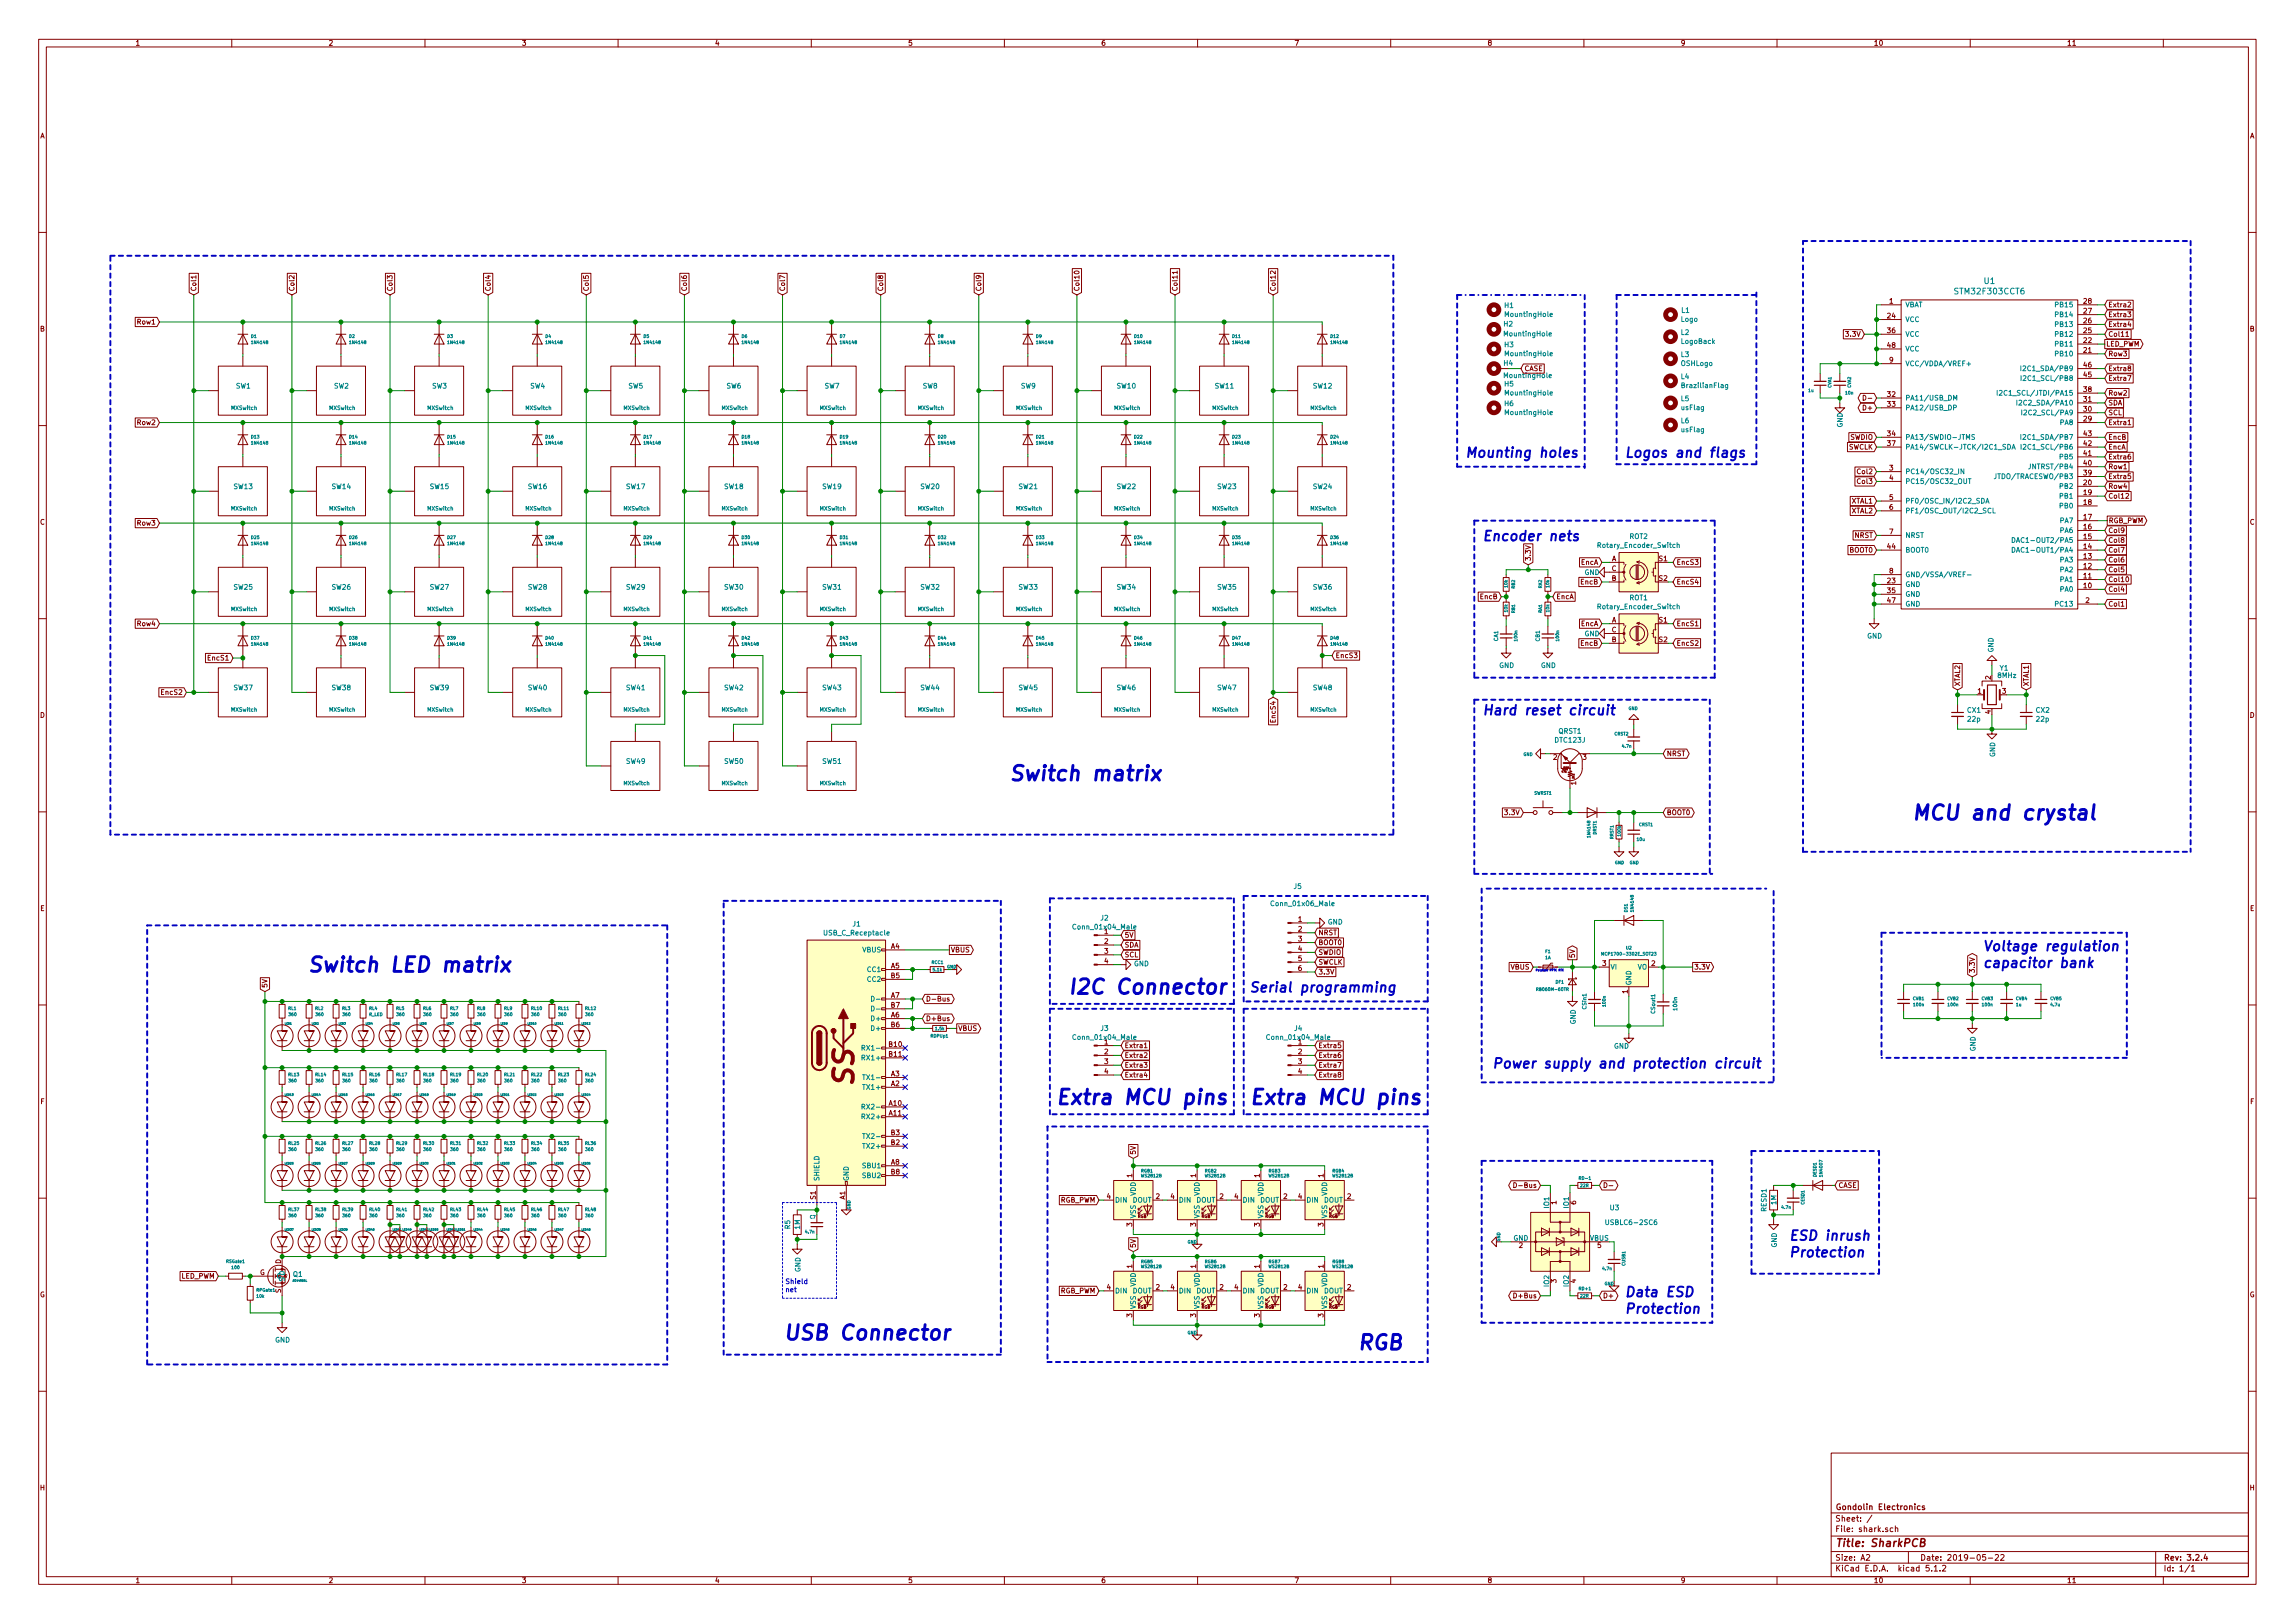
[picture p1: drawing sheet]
<svg xmlns="http://www.w3.org/2000/svg" width="594mm" height="420mm" viewBox="0 0 594 420" stroke-linecap="round" stroke-linejoin="round" font-family="sans-serif">
<defs><g id="words">
<text font-size="7.1" fill="#840000" x="221" y="280.5" transform="rotate(-90 221 280.5)">SS</text>
<g font-size="5.3" fill="#0000c2">
<text x="261" y="202.2">Switch matrix</text>
<text x="494.7" y="212.3">MCU and crystal</text>
<text x="79.4" y="251.7">Switch LED matrix</text>
<text x="276.2" y="257.4">I2C Connector</text>
<text x="273" y="286">Extra MCU pins</text>
<text x="323.2" y="286">Extra MCU pins</text>
<text x="202.6" y="346.9">USB Connector</text>
<text x="351.2" y="349.5">RGB</text>
</g>
<g font-size="3.5" fill="#0000c2">
<text x="379.1" y="118.5">Mounting holes</text>
<text x="420.4" y="118.5">Logos and flags</text>
<text x="383.5" y="140">Encoder nets</text>
<text x="383.5" y="185.1">Hard reset circuit</text>
<text x="513.1" y="246.2">Voltage regulation</text>
<text x="513.1" y="250.5">capacitor bank</text>
<text x="323.2" y="256.9">Serial programming</text>
<text x="386.1" y="276.6">Power supply and protection circuit</text>
<text x="462.9" y="321.1">ESD inrush</text>
<text x="462.9" y="325.5">Protection</text>
<text x="420.4" y="335.8">Data ESD</text>
<text x="420.4" y="340.1">Protection</text>
</g>
<text font-size="2.8" fill="#840000" x="475" y="400.4">Title: SharkPCB</text>
<g font-size="2.1" fill="#008484">
<text x="506.4" y="76.2">STM32F303CCT6</text>
<text x="513.6" y="73.5">U1</text>
</g>
<g font-size="2.1" fill="#840000">
<text x="475" y="393.9">Sheet: /</text>
<text x="475" y="390.9">Gondolin Electronics</text>
<text x="475" y="396.6">File: shark.sch</text>
<text x="475" y="406.8">KiCad E.D.A. kicad 5.1.2</text>
<text x="475" y="404">Size: A2</text>
<text x="497" y="404">Date: 2019-05-22</text>
<text x="560" y="404">Rev: 3.2.4</text>
<text x="560" y="406.8">Id: 1/1</text>
</g>
<g font-size="1.8" fill="#840000">
<text x="35" y="11.8">1</text>
<text x="85" y="11.8">2</text>
<text x="135" y="11.8">3</text>
<text x="185" y="11.8">4</text>
<text x="235" y="11.8">5</text>
<text x="285" y="11.8">6</text>
<text x="335" y="11.8">7</text>
<text x="385" y="11.8">8</text>
<text x="435" y="11.8">9</text>
<text x="485" y="11.8">10</text>
<text x="535" y="11.8">11</text>
<text x="10.4" y="35.8">A</text>
<text x="582.4" y="35.8">A</text>
<text x="50.8" y="75.5" transform="rotate(-90 50.8 75.5)">Col1</text>
<text x="76.2" y="75.5" transform="rotate(-90 76.2 75.5)">Col2</text>
<text x="101.6" y="75.5" transform="rotate(-90 101.6 75.5)">Col3</text>
<text x="127" y="75.5" transform="rotate(-90 127 75.5)">Col4</text>
<text x="152.4" y="75.5" transform="rotate(-90 152.4 75.5)">Col5</text>
<text x="177.8" y="75.5" transform="rotate(-90 177.8 75.5)">Col6</text>
<text x="203.2" y="75.5" transform="rotate(-90 203.2 75.5)">Col7</text>
<text x="228.6" y="75.5" transform="rotate(-90 228.6 75.5)">Col8</text>
<text x="254" y="75.5" transform="rotate(-90 254 75.5)">Col9</text>
<text x="279.4" y="75.5" transform="rotate(-90 279.4 75.5)">Col10</text>
<text x="304.8" y="75.5" transform="rotate(-90 304.8 75.5)">Col11</text>
<text x="330.2" y="75.5" transform="rotate(-90 330.2 75.5)">Col12</text>
<text x="35.7" y="84">Row1</text>
<text x="488.6" y="82.4">24</text>
<text x="489.1" y="78.6">1</text>
<text x="539.4" y="83.7">26</text>
<text x="539.4" y="81.1">27</text>
<text x="539.4" y="78.6">28</text>
<text x="545.7" y="79.5">Extra2</text>
<text x="545.7" y="82.1">Extra3</text>
<text x="10.4" y="85.8">B</text>
<text x="478.1" y="87.2">3.3V</text>
<text x="488.6" y="86.2">36</text>
<text x="539.4" y="88.8">22</text>
<text x="539.4" y="86.2">25</text>
<text x="545.1" y="89.7">LED_PWM</text>
<text x="545.7" y="87.2">Col11</text>
<text x="545.7" y="84.6">Extra4</text>
<text x="582.4" y="85.8">B</text>
<text x="488.6" y="90">48</text>
<text x="489.1" y="93.8">9</text>
<text x="539.4" y="91.3">21</text>
<text x="539.4" y="95.1">46</text>
<text x="545.7" y="92.2">Row3</text>
<text x="394.5" y="96.1">CASE</text>
<text x="539.4" y="101.5">38</text>
<text x="539.4" y="97.7">45</text>
<text x="545.7" y="96.1">Extra8</text>
<text x="545.7" y="98.6">Extra7</text>
<text x="482.6" y="106.2">D+</text>
<text x="488.6" y="102.7">32</text>
<text x="488.6" y="105.3">33</text>
<text x="539.4" y="106.5">30</text>
<text x="539.4" y="104">31</text>
<text x="545.7" y="102.4">Row2</text>
<text x="545.7" y="107.5">SCL</text>
<text x="545.7" y="104.9">SDA</text>
<text x="35.7" y="110">Row2</text>
<text x="478.9" y="113.8">SWDIO</text>
<text x="488.6" y="112.9">34</text>
<text x="539.4" y="109.1">29</text>
<text x="539.4" y="112.9">43</text>
<text x="545.7" y="113.8">EncB</text>
<text x="545.7" y="110">Extra1</text>
<text x="478.5" y="116.4">SWCLK</text>
<text x="488.6" y="115.4">37</text>
<text x="539.4" y="118">41</text>
<text x="539.4" y="115.4">42</text>
<text x="545.7" y="116.4">EncA</text>
<text x="545.7" y="118.9">Extra6</text>
<text x="481.1" y="122.7">Col2</text>
<text x="481.1" y="125.3">Col3</text>
<text x="489.1" y="121.8">3</text>
<text x="489.1" y="124.3">4</text>
<text x="539.4" y="125.6">20</text>
<text x="539.4" y="123.1">39</text>
<text x="539.4" y="120.5">40</text>
<text x="545.7" y="121.5">Row1</text>
<text x="545.7" y="124">Extra5</text>
<text x="479.3" y="130.3">XTAL1</text>
<text x="489.1" y="129.4">5</text>
<text x="489.1" y="131.9">6</text>
<text x="539.4" y="130.7">18</text>
<text x="539.4" y="128.1">19</text>
<text x="545.7" y="126.5">Row4</text>
<text x="545.7" y="129.1">Col12</text>
<text x="10.4" y="135.8">C</text>
<text x="35.7" y="136.1">Row3</text>
<text x="479.3" y="132.9">XTAL2</text>
<text x="539.4" y="137">16</text>
<text x="539.4" y="134.5">17</text>
<text x="545.7" y="138">Col9</text>
<text x="545.8" y="135.4">RGB_PWM</text>
<text x="582.4" y="135.8">C</text>
<text x="478.8" y="143">BOOT0</text>
<text x="480.1" y="139.2">NRST</text>
<text x="488.6" y="142.1">44</text>
<text x="489.1" y="138.3">7</text>
<text x="539.4" y="142.1">14</text>
<text x="539.4" y="139.6">15</text>
<text x="545.7" y="143">Col7</text>
<text x="545.7" y="140.5">Col8</text>
<text x="396.2" y="145.4" transform="rotate(-90 396.2 145.4)">3.3V</text>
<text x="409.3" y="146.2">EncA</text>
<text x="417.2" y="145.3">A</text>
<text x="417.2" y="147.8">C</text>
<text x="429.5" y="145.3">S1</text>
<text x="433.9" y="146.2">EncS3</text>
<text x="489.1" y="148.5">8</text>
<text x="539.4" y="149.7">11</text>
<text x="539.4" y="147.2">12</text>
<text x="539.4" y="144.6">13</text>
<text x="545.7" y="148.1">Col5</text>
<text x="545.7" y="145.6">Col6</text>
<text x="383.3" y="155.1">EncB</text>
<text x="402.8" y="155.1">EncA</text>
<text x="409.3" y="151.3">EncB</text>
<text x="417.2" y="150.4">B</text>
<text x="429.5" y="150.4">S2</text>
<text x="433.9" y="151.3">EncS4</text>
<text x="488.6" y="151">23</text>
<text x="488.6" y="153.5">35</text>
<text x="539.4" y="152.3">10</text>
<text x="545.7" y="150.7">Col10</text>
<text x="545.7" y="153.2">Col4</text>
<text x="417.2" y="161.2">A</text>
<text x="429.5" y="161.2">S1</text>
<text x="488.6" y="156.1">47</text>
<text x="539.9" y="156.1">2</text>
<text x="545.7" y="157">Col1</text>
<text x="35.7" y="162.1">Row4</text>
<text x="409.3" y="162.1">EncA</text>
<text x="409.3" y="167.2">EncB</text>
<text x="417.2" y="166.2">B</text>
<text x="417.2" y="163.7">C</text>
<text x="429.5" y="166.2">S2</text>
<text x="433.9" y="167.2">EncS2</text>
<text x="433.9" y="162.1">EncS1</text>
<text x="54.1" y="171">EncS1</text>
<text x="345.6" y="170.3">EncS3</text>
<text x="42" y="179.9">EncS2</text>
<text x="507.4" y="177.8" transform="rotate(-90 507.4 177.8)">XTAL2</text>
<text x="512" y="179.6">1</text>
<text x="515.3" y="175.9" transform="rotate(-90 515.3 175.9)">2</text>
<text x="518.3" y="179.6">3</text>
<text x="525.1" y="177.8" transform="rotate(-90 525.1 177.8)">XTAL1</text>
<text x="10.4" y="185.8">D</text>
<text x="515.3" y="184.8" transform="rotate(-90 515.3 184.8)">4</text>
<text x="582.4" y="185.8">D</text>
<text x="330.2" y="186.8" transform="rotate(-90 330.2 186.8)">EncS4</text>
<text x="402.1" y="196.7">2</text>
<text x="409.7" y="196.7">3</text>
<text x="431.4" y="195.7">NRST</text>
<text x="408" y="203.2" transform="rotate(-90 408 203.2)">1</text>
<text x="389.9" y="211">3.3V</text>
<text x="431.4" y="211">BOOT0</text>
<text x="10.4" y="235.8">E</text>
<text x="336.1" y="238.6">1</text>
<text x="582.4" y="235.8">E</text>
<text x="230.7" y="245.6">A4</text>
<text x="285.9" y="241.8">1</text>
<text x="285.9" y="244.3">2</text>
<text x="291" y="242.7">5V</text>
<text x="291" y="245.3">SDA</text>
<text x="336.1" y="241.2">2</text>
<text x="336.1" y="243.7">3</text>
<text x="341.2" y="244.6">BOOT0</text>
<text x="341.2" y="242.1">NRST</text>
<text x="230.7" y="250.7">A5</text>
<text x="246" y="246.5">VBUS</text>
<text x="285.9" y="246.9">3</text>
<text x="285.9" y="249.4">4</text>
<text x="291" y="247.8">SCL</text>
<text x="336.1" y="246.2">4</text>
<text x="336.1" y="248.8">5</text>
<text x="336.1" y="251.3">6</text>
<text x="341.2" y="249.7">SWCLK</text>
<text x="341.2" y="247.2">SWDIO</text>
<text x="391.1" y="251">VBUS</text>
<text x="407.7" y="248.1" transform="rotate(-90 407.7 248.1)">5V</text>
<text x="414.8" y="250.1">3</text>
<text x="427.5" y="250.1">2</text>
<text x="438.5" y="251">3.3V</text>
<text x="69.2" y="255.9" transform="rotate(-90 69.2 255.9)">5V</text>
<text x="230.7" y="253.2">B5</text>
<text x="341.2" y="252.3">3.3V</text>
<text x="421.3" y="257.2" transform="rotate(-90 421.3 257.2)">1</text>
<text x="511.2" y="252.1" transform="rotate(-90 511.2 252.1)">3.3V</text>
<text x="230.7" y="263.4">A6</text>
<text x="230.7" y="258.3">A7</text>
<text x="230.7" y="260.8">B7</text>
<text x="239.6" y="259.2">D-Bus</text>
<text x="230.7" y="265.9">B6</text>
<text x="239.6" y="264.3">D+Bus</text>
<text x="248" y="266.9">VBUS</text>
<text x="230.1" y="271">B10</text>
<text x="230.1" y="273.5">B11</text>
<text x="285.9" y="270.4">1</text>
<text x="285.9" y="272.9">2</text>
<text x="285.9" y="275.5">3</text>
<text x="291" y="271.3">Extra1</text>
<text x="291" y="273.9">Extra2</text>
<text x="336.1" y="270.4">1</text>
<text x="336.1" y="272.9">2</text>
<text x="336.1" y="275.5">3</text>
<text x="341.2" y="271.3">Extra5</text>
<text x="341.2" y="273.9">Extra6</text>
<text x="230.7" y="281.2">A2</text>
<text x="230.7" y="278.6">A3</text>
<text x="285.9" y="278">4</text>
<text x="291" y="276.4">Extra3</text>
<text x="291" y="278.9">Extra4</text>
<text x="336.1" y="278">4</text>
<text x="341.2" y="276.4">Extra7</text>
<text x="341.2" y="278.9">Extra8</text>
<text x="10.5" y="285.8">F</text>
<text x="230.1" y="286.2">A10</text>
<text x="582.5" y="285.8">F</text>
<text x="230.1" y="288.8">A11</text>
<text x="230.7" y="293.9">B3</text>
<text x="230.7" y="296.4">B2</text>
<text x="294" y="299.1" transform="rotate(-90 294 299.1)">5V</text>
<text x="230.7" y="301.5">A8</text>
<text x="230.7" y="304">B8</text>
<text x="293.1" y="304.8" transform="rotate(-90 293.1 304.8)">1</text>
<text x="309.6" y="304.8" transform="rotate(-90 309.6 304.8)">1</text>
<text x="326.1" y="304.8" transform="rotate(-90 326.1 304.8)">1</text>
<text x="342.6" y="304.8" transform="rotate(-90 342.6 304.8)">1</text>
<text x="211.2" y="310.5" transform="rotate(-90 211.2 310.5)">S1</text>
<text x="218.8" y="310.5" transform="rotate(-90 218.8 310.5)">A1</text>
<text x="274.4" y="311.3">RGB_PWM</text>
<text x="286.5" y="310.4">4</text>
<text x="299.2" y="310.4">2</text>
<text x="303" y="310.4">4</text>
<text x="315.7" y="310.4">2</text>
<text x="319.6" y="310.4">4</text>
<text x="332.3" y="310.4">2</text>
<text x="336.1" y="310.4">4</text>
<text x="348.8" y="310.4">2</text>
<text x="392.7" y="307.5">D-Bus</text>
<text x="402.9" y="311.8" transform="rotate(-90 402.9 311.8)">1</text>
<text x="408" y="311.8" transform="rotate(-90 408 311.8)">6</text>
<text x="475.8" y="307.5">CASE</text>
<text x="293.1" y="317.5" transform="rotate(-90 293.1 317.5)">3</text>
<text x="309.6" y="317.5" transform="rotate(-90 309.6 317.5)">3</text>
<text x="326.1" y="317.5" transform="rotate(-90 326.1 317.5)">3</text>
<text x="342.6" y="317.5" transform="rotate(-90 342.6 317.5)">3</text>
<text x="294" y="323.2" transform="rotate(-90 294 323.2)">5V</text>
<text x="393.2" y="323.1">2</text>
<text x="413.5" y="323.1">5</text>
<text x="72.7" y="327.2" transform="rotate(-90 72.7 327.2)">D</text>
<text x="293.1" y="328.3" transform="rotate(-90 293.1 328.3)">1</text>
<text x="309.6" y="328.3" transform="rotate(-90 309.6 328.3)">1</text>
<text x="326.1" y="328.3" transform="rotate(-90 326.1 328.3)">1</text>
<text x="342.6" y="328.3" transform="rotate(-90 342.6 328.3)">1</text>
<text x="10.3" y="335.8">G</text>
<text x="46.8" y="331">LED_PWM</text>
<text x="67.3" y="330.1">G</text>
<text x="72.7" y="334.8" transform="rotate(-90 72.7 334.8)">S</text>
<text x="274.4" y="334.8">RGB_PWM</text>
<text x="286.5" y="333.9">4</text>
<text x="299.2" y="333.9">2</text>
<text x="303" y="333.9">4</text>
<text x="315.7" y="333.9">2</text>
<text x="319.6" y="333.9">4</text>
<text x="332.3" y="333.9">2</text>
<text x="336.1" y="333.9">4</text>
<text x="348.8" y="333.9">2</text>
<text x="402.9" y="332.1" transform="rotate(-90 402.9 332.1)">3</text>
<text x="408" y="332.1" transform="rotate(-90 408 332.1)">4</text>
<text x="582.3" y="335.8">G</text>
<text x="293.1" y="341" transform="rotate(-90 293.1 341)">3</text>
<text x="309.6" y="341" transform="rotate(-90 309.6 341)">3</text>
<text x="326.1" y="341" transform="rotate(-90 326.1 341)">3</text>
<text x="342.6" y="341" transform="rotate(-90 342.6 341)">3</text>
<text x="392.3" y="336.1">D+Bus</text>
<text x="414.9" y="336.1">D+</text>
<text x="10.4" y="385.8">H</text>
<text x="582.4" y="385.8">H</text>
<text x="35" y="409.8">1</text>
<text x="85" y="409.8">2</text>
<text x="135" y="409.8">3</text>
<text x="185" y="409.8">4</text>
<text x="235" y="409.8">5</text>
<text x="285" y="409.8">6</text>
<text x="335" y="409.8">7</text>
<text x="385" y="409.8">8</text>
<text x="435" y="409.8">9</text>
<text x="485" y="409.8">10</text>
<text x="535" y="409.8">11</text>
</g>
<g font-size="1.8" fill="#008484">
<text x="389.5" y="79.7">H1</text>
<text x="389.8" y="82">MountingHole</text>
<text x="435.2" y="83.3">Logo</text>
<text x="435.3" y="81">L1</text>
<text x="493.1" y="79.5">VBAT</text>
<text x="493.1" y="83.4">VCC</text>
<text x="532.4" y="82.1">PB14</text>
<text x="532.4" y="79.5">PB15</text>
<text x="389.3" y="84.5">H2</text>
<text x="389.5" y="89.9">H3</text>
<text x="389.6" y="87.1">MountingHole</text>
<text x="435.2" y="86.7">L2</text>
<text x="435.3" y="89">LogoBack</text>
<text x="493.1" y="87.2">VCC</text>
<text x="532.4" y="89.7">PB11</text>
<text x="532.4" y="87.2">PB12</text>
<text x="532.4" y="84.6">PB13</text>
<text x="389.3" y="94.7">H4</text>
<text x="389.8" y="92.2">MountingHole</text>
<text x="435.2" y="92.4">L3</text>
<text x="435.2" y="94.7">OSHLogo</text>
<text x="493.1" y="91">VCC</text>
<text x="493.1" y="94.8">VCC/VDDA/VREF+</text>
<text x="532.4" y="92.2">PB10</text>
<text x="61.1" y="100.6">SW1</text>
<text x="86.5" y="100.6">SW2</text>
<text x="111.9" y="100.6">SW3</text>
<text x="137.3" y="100.6">SW4</text>
<text x="162.7" y="100.6">SW5</text>
<text x="188.1" y="100.6">SW6</text>
<text x="213.5" y="100.6">SW7</text>
<text x="238.9" y="100.6">SW8</text>
<text x="264.3" y="100.6">SW9</text>
<text x="289.2" y="100.6">SW10</text>
<text x="314.6" y="100.6">SW11</text>
<text x="340" y="100.6">SW12</text>
<text x="389.5" y="100">H5</text>
<text x="389.6" y="97.9">MountingHole</text>
<text x="435.2" y="98.1">L4</text>
<text x="435.8" y="100.4">BrazilianFlag</text>
<text x="524.4" y="96.1">I2C1_SDA/PB9</text>
<text x="524.6" y="98.6">I2C1_SCL/PB8</text>
<text x="389.5" y="105.1">H6</text>
<text x="389.8" y="102.4">MountingHole</text>
<text x="389.8" y="107.4">MountingHole</text>
<text x="435.2" y="103.9">L5</text>
<text x="435.3" y="106.2">usFlag</text>
<text x="493.1" y="103.7">PA11/USB_DM</text>
<text x="493.1" y="106.2">PA12/USB_DP</text>
<text x="519.3" y="102.4">I2C1_SCL/JTDI/PA15</text>
<text x="523.5" y="104.9">I2C2_SDA/PA10</text>
<text x="524.6" y="107.5">I2C2_SCL/PA9</text>
<text x="435.2" y="109.6">L6</text>
<text x="435.3" y="111.9">usFlag</text>
<text x="477" y="110.7" transform="rotate(-90 477 110.7)">GND</text>
<text x="493.1" y="113.8">PA13/SWDIO-JTMS</text>
<text x="524.4" y="113.8">I2C1_SDA/PB7</text>
<text x="533.4" y="110">PA8</text>
<text x="493.1" y="116.4">PA14/SWCLK-JTCK/I2C1_SDA</text>
<text x="524.6" y="116.4">I2C1_SCL/PB6</text>
<text x="533.4" y="118.9">PB5</text>
<text x="493.1" y="122.7">PC14/OSC32_IN</text>
<text x="493.1" y="125.3">PC15/OSC32_OUT</text>
<text x="517.4" y="124">JTDO/TRACESWO/PB3</text>
<text x="526" y="121.5">JNTRST/PB4</text>
<text x="60.6" y="126.6">SW13</text>
<text x="86" y="126.6">SW14</text>
<text x="111.4" y="126.6">SW15</text>
<text x="136.8" y="126.6">SW16</text>
<text x="162.2" y="126.6">SW17</text>
<text x="187.6" y="126.6">SW18</text>
<text x="213" y="126.6">SW19</text>
<text x="238.4" y="126.6">SW20</text>
<text x="263.8" y="126.6">SW21</text>
<text x="289.2" y="126.6">SW22</text>
<text x="315.2" y="126.6">SW23</text>
<text x="340" y="126.6">SW24</text>
<text x="493.1" y="130.3">PF0/OSC_IN/I2C2_SDA</text>
<text x="533.4" y="131.6">PB0</text>
<text x="533.4" y="129.1">PB1</text>
<text x="533.4" y="126.5">PB2</text>
<text x="493.1" y="132.9">PF1/OSC_OUT/I2C2_SCL</text>
<text x="533.4" y="138">PA6</text>
<text x="533.4" y="135.4">PA7</text>
<text x="414" y="141.8">Rotary_Encoder_Switch</text>
<text x="421.8" y="139.5">ROT2</text>
<text x="493.1" y="143">BOOT0</text>
<text x="493.1" y="139.2">NRST</text>
<text x="522.8" y="143">DAC1-OUT1/PA4</text>
<text x="522.8" y="140.5">DAC1-OUT2/PA5</text>
<text x="410.2" y="148.8">GND</text>
<text x="493.1" y="149.4">GND/VSSA/VREF-</text>
<text x="533.4" y="148.1">PA2</text>
<text x="533.4" y="145.6">PA3</text>
<text x="60.6" y="152.6">SW25</text>
<text x="86" y="152.6">SW26</text>
<text x="111.4" y="152.6">SW27</text>
<text x="136.8" y="152.6">SW28</text>
<text x="162.2" y="152.6">SW29</text>
<text x="187.6" y="152.6">SW30</text>
<text x="213" y="152.6">SW31</text>
<text x="238.4" y="152.6">SW32</text>
<text x="263.8" y="152.6">SW33</text>
<text x="289.2" y="152.6">SW34</text>
<text x="315.2" y="152.6">SW35</text>
<text x="340" y="152.6">SW36</text>
<text x="421.8" y="155.4">ROT1</text>
<text x="493.1" y="151.9">GND</text>
<text x="493.1" y="154.5">GND</text>
<text x="533.4" y="153.2">PA0</text>
<text x="533.4" y="150.7">PA1</text>
<text x="414" y="157.7">Rotary_Encoder_Switch</text>
<text x="493.1" y="157">GND</text>
<text x="532.4" y="157">PC13</text>
<text x="410.2" y="164.7">GND</text>
<text x="483.3" y="165.3">GND</text>
<text x="388.1" y="172.9">GND</text>
<text x="398.9" y="172.9">GND</text>
<text x="516" y="168.9" transform="rotate(-90 516 168.9)">GND</text>
<text x="517.7" y="173.6">Y1</text>
<text x="60.6" y="178.7">SW37</text>
<text x="86" y="178.7">SW38</text>
<text x="111.4" y="178.7">SW39</text>
<text x="136.8" y="178.7">SW40</text>
<text x="162.2" y="178.7">SW41</text>
<text x="187.6" y="178.7">SW42</text>
<text x="213" y="178.7">SW43</text>
<text x="238.4" y="178.7">SW44</text>
<text x="263.8" y="178.7">SW45</text>
<text x="289.2" y="178.7">SW46</text>
<text x="315.2" y="178.7">SW47</text>
<text x="340" y="178.7">SW48</text>
<text x="517.2" y="175.5">8MHz</text>
<text x="509.3" y="184.5">CX1</text>
<text x="527.1" y="184.5">CX2</text>
<text x="403.5" y="189.9">QRST1</text>
<text x="509.4" y="186.8">22p</text>
<text x="527.2" y="186.8">22p</text>
<text x="162.2" y="197.7">SW49</text>
<text x="187.6" y="197.7">SW50</text>
<text x="213" y="197.7">SW51</text>
<text x="402.6" y="192.2">DTC123J</text>
<text x="516.5" y="196" transform="rotate(-90 516.5 196)">GND</text>
<text x="334.9" y="230.1">J5</text>
<text x="220.8" y="239.8">J1</text>
<text x="284.9" y="238.3">J2</text>
<text x="329.5" y="234.6">Conn_01x06_Male</text>
<text x="343.7" y="239.3">GND</text>
<text x="213.6" y="242.2">USB_C_Receptacle</text>
<text x="278.2" y="240.6">Conn_01x04_Male</text>
<text x="223.3" y="246.5">VBUS</text>
<text x="224.7" y="251.6">CC1</text>
<text x="293.5" y="250.1">GND</text>
<text x="416.8" y="251">VI</text>
<text x="423.9" y="251">VO</text>
<text x="224.7" y="254.2">CC2</text>
<text x="422.3" y="255.2" transform="rotate(-90 422.3 255.2)">GND</text>
<text x="225.9" y="264.3">D+</text>
<text x="225.9" y="266.9">D+</text>
<text x="278.2" y="269.2">Conn_01x04_Male</text>
<text x="284.9" y="266.9">J3</text>
<text x="328.4" y="269.2">Conn_01x04_Male</text>
<text x="335.1" y="266.9">J4</text>
<text x="407.9" y="265.2" transform="rotate(-90 407.9 265.2)">GND</text>
<text x="223.7" y="274.5">RX1+</text>
<text x="224.2" y="271.9">RX1-</text>
<text x="417.8" y="271.5">GND</text>
<text x="511.4" y="272.2" transform="rotate(-90 511.4 272.2)">GND</text>
<text x="224.4" y="279.6">TX1-</text>
<text x="224" y="282.1">TX1+</text>
<text x="224.2" y="287.2">RX2-</text>
<text x="223.7" y="289.7">RX2+</text>
<text x="224" y="297.3">TX2+</text>
<text x="224.4" y="294.8">TX2-</text>
<text x="212.1" y="305.9" transform="rotate(-90 212.1 305.9)">SHIELD</text>
<text x="219.7" y="305.9" transform="rotate(-90 219.7 305.9)">GND</text>
<text x="223.5" y="302.4">SBU1</text>
<text x="223.5" y="305">SBU2</text>
<text x="288.5" y="311.3">DIN</text>
<text x="293.2" y="311.3">DOUT</text>
<text x="294" y="309.6" transform="rotate(-90 294 309.6)">VDD</text>
<text x="305.1" y="311.3">DIN</text>
<text x="309.7" y="311.3">DOUT</text>
<text x="310.5" y="309.6" transform="rotate(-90 310.5 309.6)">VDD</text>
<text x="321.6" y="311.3">DIN</text>
<text x="326.2" y="311.3">DOUT</text>
<text x="327" y="309.6" transform="rotate(-90 327 309.6)">VDD</text>
<text x="338.1" y="311.3">DIN</text>
<text x="342.7" y="311.3">DOUT</text>
<text x="343.5" y="309.6" transform="rotate(-90 343.5 309.6)">VDD</text>
<text x="459.8" y="311.9" transform="rotate(-90 459.8 311.9)">1M</text>
<text x="294" y="315.5" transform="rotate(-90 294 315.5)">VSS</text>
<text x="310.5" y="315.5" transform="rotate(-90 310.5 315.5)">VSS</text>
<text x="327" y="315.5" transform="rotate(-90 327 315.5)">VSS</text>
<text x="343.5" y="315.5" transform="rotate(-90 343.5 315.5)">VSS</text>
<text x="401" y="312.7" transform="rotate(-90 401 312.7)">IO1</text>
<text x="406.1" y="312.7" transform="rotate(-90 406.1 312.7)">IO1</text>
<text x="416.2" y="317.1">USBLC6-2SC6</text>
<text x="416.8" y="313.3">U3</text>
<text x="457.3" y="313.6" transform="rotate(-90 457.3 313.6)">RESD1</text>
<text x="204.5" y="318.2" transform="rotate(-90 204.5 318.2)">R5</text>
<text x="207.1" y="318.2" transform="rotate(-90 207.1 318.2)">1M</text>
<text x="391.7" y="321.2">GND</text>
<text x="411.6" y="321.2">VBUS</text>
<text x="459.9" y="323" transform="rotate(-90 459.9 323)">GND</text>
<text x="207.2" y="329.4" transform="rotate(-90 207.2 329.4)">GND</text>
<text x="71.5" y="331">G</text>
<text x="73.7" y="331.9" transform="rotate(-90 73.7 331.9)">S D</text>
<text x="75.9" y="330.5">Q1</text>
<text x="288.5" y="334.8">DIN</text>
<text x="293.2" y="334.8">DOUT</text>
<text x="294" y="333.1" transform="rotate(-90 294 333.1)">VDD</text>
<text x="305.1" y="334.8">DIN</text>
<text x="309.7" y="334.8">DOUT</text>
<text x="310.5" y="333.1" transform="rotate(-90 310.5 333.1)">VDD</text>
<text x="321.6" y="334.8">DIN</text>
<text x="326.2" y="334.8">DOUT</text>
<text x="327" y="333.1" transform="rotate(-90 327 333.1)">VDD</text>
<text x="338.1" y="334.8">DIN</text>
<text x="342.7" y="334.8">DOUT</text>
<text x="343.5" y="333.1" transform="rotate(-90 343.5 333.1)">VDD</text>
<text x="401" y="333.1" transform="rotate(-90 401 333.1)">IO2</text>
<text x="406.1" y="333.1" transform="rotate(-90 406.1 333.1)">IO2</text>
<text x="294" y="339" transform="rotate(-90 294 339)">VSS</text>
<text x="310.5" y="339" transform="rotate(-90 310.5 339)">VSS</text>
<text x="327" y="339" transform="rotate(-90 327 339)">VSS</text>
<text x="343.5" y="339" transform="rotate(-90 343.5 339)">VSS</text>
<text x="71.2" y="347.5">GND</text>
</g>
<g font-size="1.8" fill="#0000c2">
<text x="203.2" y="332.4">Shield</text>
<text x="203.2" y="334.5">net</text>
</g>
<g font-size="1.4" fill="#008484">
<text x="59.9" y="106.1">MXSwitch</text>
<text x="85.3" y="106.1">MXSwitch</text>
<text x="110.7" y="106.1">MXSwitch</text>
<text x="136.1" y="106.1">MXSwitch</text>
<text x="161.5" y="106.1">MXSwitch</text>
<text x="186.9" y="106.1">MXSwitch</text>
<text x="212.3" y="106.1">MXSwitch</text>
<text x="237.7" y="106.1">MXSwitch</text>
<text x="263.1" y="106.1">MXSwitch</text>
<text x="288.5" y="106.1">MXSwitch</text>
<text x="313.9" y="106.1">MXSwitch</text>
<text x="339.3" y="106.1">MXSwitch</text>
<text x="59.9" y="132.1">MXSwitch</text>
<text x="85.3" y="132.1">MXSwitch</text>
<text x="110.7" y="132.1">MXSwitch</text>
<text x="136.1" y="132.1">MXSwitch</text>
<text x="161.5" y="132.1">MXSwitch</text>
<text x="186.9" y="132.1">MXSwitch</text>
<text x="212.3" y="132.1">MXSwitch</text>
<text x="237.7" y="132.1">MXSwitch</text>
<text x="263.1" y="132.1">MXSwitch</text>
<text x="288.5" y="132.1">MXSwitch</text>
<text x="313.9" y="132.1">MXSwitch</text>
<text x="339.3" y="132.1">MXSwitch</text>
<text x="59.9" y="158.2">MXSwitch</text>
<text x="85.3" y="158.2">MXSwitch</text>
<text x="110.7" y="158.2">MXSwitch</text>
<text x="136.1" y="158.2">MXSwitch</text>
<text x="161.5" y="158.2">MXSwitch</text>
<text x="186.9" y="158.2">MXSwitch</text>
<text x="212.3" y="158.2">MXSwitch</text>
<text x="237.7" y="158.2">MXSwitch</text>
<text x="263.1" y="158.2">MXSwitch</text>
<text x="288.5" y="158.2">MXSwitch</text>
<text x="313.9" y="158.2">MXSwitch</text>
<text x="339.3" y="158.2">MXSwitch</text>
<text x="387.8" y="166" transform="rotate(-90 387.8 166)">CA1</text>
<text x="398.6" y="166" transform="rotate(-90 398.6 166)">CB1</text>
<text x="59.9" y="184.2">MXSwitch</text>
<text x="85.3" y="184.2">MXSwitch</text>
<text x="110.7" y="184.2">MXSwitch</text>
<text x="136.1" y="184.2">MXSwitch</text>
<text x="161.5" y="184.2">MXSwitch</text>
<text x="186.9" y="184.2">MXSwitch</text>
<text x="212.3" y="184.2">MXSwitch</text>
<text x="237.7" y="184.2">MXSwitch</text>
<text x="263.1" y="184.2">MXSwitch</text>
<text x="288.5" y="184.2">MXSwitch</text>
<text x="313.9" y="184.2">MXSwitch</text>
<text x="339.3" y="184.2">MXSwitch</text>
<text x="161.5" y="203.3">MXSwitch</text>
<text x="186.9" y="203.3">MXSwitch</text>
<text x="212.3" y="203.3">MXSwitch</text>
<text x="410.6" y="261.2" transform="rotate(-90 410.6 261.2)">CSin1</text>
<text x="428.4" y="262.3" transform="rotate(-90 428.4 262.3)">CSout1</text>
<text x="434.1" y="261.5" transform="rotate(-90 434.1 261.5)">100n</text>
</g>
<g font-size="1.1" fill="#008484">
<text x="65" y="87.4">D1</text>
<text x="65.3" y="89">1N4148</text>
<text x="90.4" y="87.4">D2</text>
<text x="90.7" y="89">1N4148</text>
<text x="115.8" y="87.4">D3</text>
<text x="116.1" y="89">1N4148</text>
<text x="141.2" y="87.4">D4</text>
<text x="141.5" y="89">1N4148</text>
<text x="166.6" y="87.4">D5</text>
<text x="166.9" y="89">1N4148</text>
<text x="192" y="87.4">D6</text>
<text x="192.3" y="89">1N4148</text>
<text x="217.4" y="87.4">D7</text>
<text x="217.7" y="89">1N4148</text>
<text x="242.8" y="87.4">D8</text>
<text x="243.1" y="89">1N4148</text>
<text x="268.2" y="87.4">D9</text>
<text x="268.5" y="89">1N4148</text>
<text x="293.7" y="87.4">D10</text>
<text x="293.9" y="89">1N4148</text>
<text x="319.1" y="87.4">D11</text>
<text x="319.3" y="89">1N4148</text>
<text x="344.5" y="87.4">D12</text>
<text x="344.7" y="89">1N4148</text>
<text x="468.1" y="101.5">1u</text>
<text x="474" y="100.4" transform="rotate(-90 474 100.4)">CVA1</text>
<text x="479.1" y="100.4" transform="rotate(-90 479.1 100.4)">CVA2</text>
<text x="477.7" y="102.1">10n</text>
<text x="65.1" y="113.5">D13</text>
<text x="90.5" y="113.5">D14</text>
<text x="115.9" y="113.5">D15</text>
<text x="141.3" y="113.5">D16</text>
<text x="166.7" y="113.5">D17</text>
<text x="192.1" y="113.5">D18</text>
<text x="217.5" y="113.5">D19</text>
<text x="242.9" y="113.5">D20</text>
<text x="268.3" y="113.5">D21</text>
<text x="293.7" y="113.5">D22</text>
<text x="319.1" y="113.5">D23</text>
<text x="344.5" y="113.5">D24</text>
<text x="65.3" y="115.1">1N4148</text>
<text x="90.7" y="115.1">1N4148</text>
<text x="116.1" y="115.1">1N4148</text>
<text x="141.5" y="115.1">1N4148</text>
<text x="166.9" y="115.1">1N4148</text>
<text x="192.3" y="115.1">1N4148</text>
<text x="217.7" y="115.1">1N4148</text>
<text x="243.1" y="115.1">1N4148</text>
<text x="268.5" y="115.1">1N4148</text>
<text x="293.9" y="115.1">1N4148</text>
<text x="319.3" y="115.1">1N4148</text>
<text x="344.7" y="115.1">1N4148</text>
<text x="65.1" y="139.5">D25</text>
<text x="65.3" y="141.1">1N4148</text>
<text x="90.5" y="139.5">D26</text>
<text x="90.7" y="141.1">1N4148</text>
<text x="115.9" y="139.5">D27</text>
<text x="116.1" y="141.1">1N4148</text>
<text x="141.3" y="139.5">D28</text>
<text x="141.5" y="141.1">1N4148</text>
<text x="166.7" y="139.5">D29</text>
<text x="166.9" y="141.1">1N4148</text>
<text x="192.1" y="139.5">D30</text>
<text x="192.3" y="141.1">1N4148</text>
<text x="217.5" y="139.5">D31</text>
<text x="217.7" y="141.1">1N4148</text>
<text x="242.9" y="139.5">D32</text>
<text x="243.1" y="141.1">1N4148</text>
<text x="268.3" y="139.5">D33</text>
<text x="268.5" y="141.1">1N4148</text>
<text x="293.7" y="139.5">D34</text>
<text x="293.9" y="141.1">1N4148</text>
<text x="319.1" y="139.5">D35</text>
<text x="319.3" y="141.1">1N4148</text>
<text x="344.5" y="139.5">D36</text>
<text x="344.7" y="141.1">1N4148</text>
<text x="390.2" y="152.1" transform="rotate(-90 390.2 152.1)">10k</text>
<text x="392.1" y="152.3" transform="rotate(-90 392.1 152.3)">RB2</text>
<text x="399.1" y="152.3" transform="rotate(-90 399.1 152.3)">RA2</text>
<text x="401" y="152.1" transform="rotate(-90 401 152.1)">10k</text>
<text x="390.2" y="158.4" transform="rotate(-90 390.2 158.4)">10k</text>
<text x="392.1" y="158.7" transform="rotate(-90 392.1 158.7)">RB1</text>
<text x="399.1" y="158.6" transform="rotate(-90 399.1 158.6)">RA1</text>
<text x="401" y="158.4" transform="rotate(-90 401 158.4)">10k</text>
<text x="65.1" y="165.5">D37</text>
<text x="65.3" y="167.1">1N4148</text>
<text x="90.5" y="165.5">D38</text>
<text x="90.7" y="167.1">1N4148</text>
<text x="115.9" y="165.5">D39</text>
<text x="116.1" y="167.1">1N4148</text>
<text x="141.3" y="165.5">D40</text>
<text x="141.5" y="167.1">1N4148</text>
<text x="166.7" y="165.5">D41</text>
<text x="166.9" y="167.1">1N4148</text>
<text x="192.1" y="165.5">D42</text>
<text x="192.3" y="167.1">1N4148</text>
<text x="217.5" y="165.5">D43</text>
<text x="217.7" y="167.1">1N4148</text>
<text x="242.9" y="165.5">D44</text>
<text x="243.1" y="167.1">1N4148</text>
<text x="268.3" y="165.5">D45</text>
<text x="268.5" y="167.1">1N4148</text>
<text x="293.7" y="165.5">D46</text>
<text x="293.9" y="167.1">1N4148</text>
<text x="319.1" y="165.5">D47</text>
<text x="319.3" y="167.1">1N4148</text>
<text x="344.5" y="165.5">D48</text>
<text x="344.7" y="167.1">1N4148</text>
<text x="392.8" y="165.9" transform="rotate(-90 392.8 165.9)">100n</text>
<text x="403.6" y="165.9" transform="rotate(-90 403.6 165.9)">100n</text>
<text x="421.5" y="183.8">GND</text>
<text x="417.9" y="190.4">CRST2</text>
<text x="394.3" y="195.7">GND</text>
<text x="420" y="193.5">4.7n</text>
<text x="397.1" y="205.7">SWRST1</text>
<text x="424.3" y="213.9">CRST1</text>
<text x="411.7" y="216.6" transform="rotate(-90 411.7 216.6)">1N4148</text>
<text x="413.2" y="216.1" transform="rotate(-90 413.2 216.1)">DRST1</text>
<text x="417.6" y="217.2" transform="rotate(-90 417.6 217.2)">RRST1</text>
<text x="419.5" y="216.4" transform="rotate(-90 419.5 216.4)">100k</text>
<text x="423.8" y="217.7">10u</text>
<text x="418" y="223.7">GND</text>
<text x="421.8" y="223.7">GND</text>
<text x="421.3" y="236.1" transform="rotate(-90 421.3 236.1)">DS1</text>
<text x="422.9" y="235.8" transform="rotate(-90 422.9 235.8)">1N4148</text>
<text x="421" y="245.8">U2</text>
<text x="241.2" y="249.5">RCC1</text>
<text x="241.6" y="251.4">5.1k</text>
<text x="400" y="248.3">1A</text>
<text x="400" y="246.7">F1</text>
<text x="415.4" y="247.3">MCP1700-3302E_SOT23</text>
<text x="398.2" y="256.5">RB060M-60TR</text>
<text x="402.7" y="254.6">DF1</text>
<text x="74.6" y="261.4">RL1</text>
<text x="74.8" y="263">360</text>
<text x="81.6" y="261.4">RL2</text>
<text x="81.8" y="263">360</text>
<text x="88.6" y="261.4">RL3</text>
<text x="88.8" y="263">360</text>
<text x="95.5" y="263">R_LED</text>
<text x="95.6" y="261.4">RL4</text>
<text x="102.6" y="261.4">RL5</text>
<text x="102.7" y="263">360</text>
<text x="109.6" y="261.4">RL6</text>
<text x="109.7" y="263">360</text>
<text x="116.5" y="261.4">RL7</text>
<text x="116.7" y="263">360</text>
<text x="123.5" y="261.4">RL8</text>
<text x="123.7" y="263">360</text>
<text x="130.5" y="261.4">RL9</text>
<text x="130.7" y="263">360</text>
<text x="137.6" y="261.4">RL10</text>
<text x="137.7" y="263">360</text>
<text x="144.6" y="261.4">RL11</text>
<text x="144.7" y="263">360</text>
<text x="151.5" y="261.4">RL12</text>
<text x="151.6" y="263">360</text>
<text x="415.6" y="260.5" transform="rotate(-90 415.6 260.5)">100n</text>
<text x="495.2" y="258.9">CVB1</text>
<text x="495.4" y="260.5">100n</text>
<text x="504.1" y="258.9">CVB2</text>
<text x="504.3" y="260.5">100n</text>
<text x="513" y="258.9">CVB3</text>
<text x="513.2" y="260.5">100n</text>
<text x="521.9" y="258.9">CVB4</text>
<text x="521.9" y="260.5">1u</text>
<text x="530.8" y="258.9">CVB5</text>
<text x="530.9" y="260.5">4.7u</text>
<text x="241" y="268.6">RDPUp1</text>
<text x="242.2" y="266.7">1.5k</text>
<text x="74.7" y="278.6">RL13</text>
<text x="74.8" y="280.2">360</text>
<text x="81.7" y="278.6">RL14</text>
<text x="81.8" y="280.2">360</text>
<text x="88.7" y="278.6">RL15</text>
<text x="88.8" y="280.2">360</text>
<text x="95.7" y="278.6">RL16</text>
<text x="95.8" y="280.2">360</text>
<text x="102.6" y="278.6">RL17</text>
<text x="102.7" y="280.2">360</text>
<text x="109.6" y="278.6">RL18</text>
<text x="109.7" y="280.2">360</text>
<text x="116.6" y="278.6">RL19</text>
<text x="116.7" y="280.2">360</text>
<text x="123.6" y="278.6">RL20</text>
<text x="123.7" y="280.2">360</text>
<text x="130.6" y="278.6">RL21</text>
<text x="130.7" y="280.2">360</text>
<text x="137.6" y="278.6">RL22</text>
<text x="137.7" y="280.2">360</text>
<text x="144.6" y="278.6">RL23</text>
<text x="144.7" y="280.2">360</text>
<text x="151.5" y="278.6">RL24</text>
<text x="151.6" y="280.2">360</text>
<text x="74.7" y="296.4">RL25</text>
<text x="74.8" y="297.9">360</text>
<text x="81.7" y="296.4">RL26</text>
<text x="81.8" y="297.9">360</text>
<text x="88.7" y="296.4">RL27</text>
<text x="88.8" y="297.9">360</text>
<text x="95.7" y="296.4">RL28</text>
<text x="95.8" y="297.9">360</text>
<text x="102.6" y="296.4">RL29</text>
<text x="102.7" y="297.9">360</text>
<text x="109.6" y="296.4">RL30</text>
<text x="109.7" y="297.9">360</text>
<text x="116.6" y="296.4">RL31</text>
<text x="116.7" y="297.9">360</text>
<text x="123.6" y="296.4">RL32</text>
<text x="123.7" y="297.9">360</text>
<text x="130.6" y="296.4">RL33</text>
<text x="130.7" y="297.9">360</text>
<text x="137.6" y="296.4">RL34</text>
<text x="137.7" y="297.9">360</text>
<text x="144.6" y="296.4">RL35</text>
<text x="144.7" y="297.9">360</text>
<text x="151.5" y="296.4">RL36</text>
<text x="151.6" y="297.9">360</text>
<text x="295.4" y="303.5">RGB1</text>
<text x="295.6" y="304.8">WS2812B</text>
<text x="311.9" y="303.5">RGB2</text>
<text x="312.1" y="304.8">WS2812B</text>
<text x="328.4" y="303.5">RGB3</text>
<text x="328.6" y="304.8">WS2812B</text>
<text x="344.9" y="303.5">RGB4</text>
<text x="345.1" y="304.8">WS2812B</text>
<text x="409" y="305.4">RD-1</text>
<text x="470.2" y="304.6" transform="rotate(-90 470.2 304.6)">DESD1</text>
<text x="471.8" y="304.4" transform="rotate(-90 471.8 304.4)">1N4007</text>
<text x="409.1" y="307.3">22R</text>
<text x="467.1" y="311.8" transform="rotate(-90 467.1 311.8)">CESD1</text>
<text x="74.7" y="313.5">RL37</text>
<text x="74.8" y="315.1">360</text>
<text x="81.7" y="313.5">RL38</text>
<text x="81.8" y="315.1">360</text>
<text x="88.7" y="313.5">RL39</text>
<text x="88.8" y="315.1">360</text>
<text x="95.7" y="313.5">RL40</text>
<text x="95.8" y="315.1">360</text>
<text x="102.6" y="313.5">RL41</text>
<text x="102.7" y="315.1">360</text>
<text x="109.6" y="313.5">RL42</text>
<text x="109.7" y="315.1">360</text>
<text x="116.6" y="313.5">RL43</text>
<text x="116.7" y="315.1">360</text>
<text x="123.6" y="313.5">RL44</text>
<text x="123.7" y="315.1">360</text>
<text x="130.6" y="313.5">RL45</text>
<text x="130.7" y="315.1">360</text>
<text x="137.6" y="313.5">RL46</text>
<text x="137.7" y="315.1">360</text>
<text x="144.6" y="313.5">RL47</text>
<text x="144.7" y="315.1">360</text>
<text x="151.5" y="313.5">RL48</text>
<text x="151.6" y="315.1">360</text>
<text x="209.7" y="315.5">C7</text>
<text x="220.1" y="313.1" transform="rotate(-90 220.1 313.1)">GND</text>
<text x="461.3" y="312.9">4.7n</text>
<text x="208.5" y="319.3">4.7n</text>
<text x="307.4" y="321.9">GND</text>
<text x="388.3" y="321.4" transform="rotate(-90 388.3 321.4)">GND</text>
<text x="58.7" y="326.9">RSGate1</text>
<text x="60" y="328.5">100</text>
<text x="295.4" y="327">RGB5</text>
<text x="295.6" y="328.3">WS2812B</text>
<text x="311.9" y="327">RGB6</text>
<text x="312.1" y="328.3">WS2812B</text>
<text x="328.4" y="327">RGB7</text>
<text x="328.6" y="328.3">WS2812B</text>
<text x="344.9" y="327">RGB8</text>
<text x="345.1" y="328.3">WS2812B</text>
<text x="414.9" y="328.8">4.7n</text>
<text x="420.7" y="327.7" transform="rotate(-90 420.7 327.7)">CUSB1</text>
<text x="66.5" y="335.9">10k</text>
<text x="66.5" y="334.4">RPGate1</text>
<text x="408.8" y="334">RD+1</text>
<text x="409.1" y="335.9">22R</text>
<text x="415.3" y="332.7">GND</text>
<text x="307.4" y="345.4">GND</text>
</g>
<text font-size="1.1" fill="#008400" x="245.1" y="250.7">GND</text>
<g font-size="1.1" fill="#840000">
<text x="294.5" y="315.3">RGB</text>
<text x="311" y="315.3">RGB</text>
<text x="327.5" y="315.3">RGB</text>
<text x="344" y="315.3">RGB</text>
<text x="294.5" y="338.8">RGB</text>
<text x="311" y="338.8">RGB</text>
<text x="327.5" y="338.8">RGB</text>
<text x="344" y="338.8">RGB</text>
</g>
<g font-size=".7" fill="#840000">
<text x="404.3" y="200">47k</text>
<text x="407.5" y="201.5" transform="rotate(-90 407.5 201.5)">2k2</text>
</g>
<text font-size=".7" fill="#0000c2" x="397.5" y="251.4">Polyfuse PPTC RTC</text>
<g font-size=".7" fill="#008484">
<text x="73.7" y="265.2">LED1</text>
<text x="80.7" y="265.2">LED2</text>
<text x="87.7" y="265.2">LED3</text>
<text x="94.7" y="265.2">LED4</text>
<text x="101.7" y="265.2">LED5</text>
<text x="108.7" y="265.2">LED6</text>
<text x="115.6" y="265.2">LED7</text>
<text x="122.6" y="265.2">LED8</text>
<text x="129.6" y="265.2">LED9</text>
<text x="136.6" y="265.2">LED10</text>
<text x="143.6" y="265.2">LED11</text>
<text x="150.6" y="265.2">LED12</text>
<text x="73.8" y="283.7">LED13</text>
<text x="80.7" y="283.7">LED14</text>
<text x="87.7" y="283.7">LED15</text>
<text x="94.7" y="283.7">LED16</text>
<text x="101.7" y="283.7">LED17</text>
<text x="108.7" y="283.7">LED18</text>
<text x="115.7" y="283.7">LED19</text>
<text x="122.7" y="283.7">LED20</text>
<text x="129.6" y="283.7">LED21</text>
<text x="136.6" y="283.7">LED22</text>
<text x="143.6" y="283.7">LED23</text>
<text x="150.6" y="283.7">LED24</text>
<text x="73.8" y="301.4">LED25</text>
<text x="80.7" y="301.4">LED26</text>
<text x="87.7" y="301.4">LED27</text>
<text x="94.7" y="301.4">LED28</text>
<text x="101.7" y="301.4">LED29</text>
<text x="108.7" y="301.4">LED30</text>
<text x="115.7" y="301.4">LED31</text>
<text x="122.7" y="301.4">LED32</text>
<text x="129.6" y="301.4">LED33</text>
<text x="136.6" y="301.4">LED34</text>
<text x="143.6" y="301.4">LED35</text>
<text x="150.6" y="301.4">LED36</text>
<text x="73.8" y="318.6">LED37</text>
<text x="80.7" y="318.6">LED38</text>
<text x="87.7" y="318.6">LED39</text>
<text x="94.7" y="318.6">LED40</text>
<text x="101.7" y="318.6">LED41 LED49</text>
<text x="108.7" y="318.6">LED42 LED50</text>
<text x="115.7" y="318.6">LED43 LED51</text>
<text x="122.7" y="318.6">LED44</text>
<text x="129.6" y="318.6">LED45</text>
<text x="136.6" y="318.6">LED46</text>
<text x="143.6" y="318.6">LED47</text>
<text x="150.6" y="318.6">LED48</text>
<text x="75.8" y="331.8">AO4406AL</text>
</g>
</g></defs>
<g fill="none" stroke="#840000" stroke-width=".26">
<path d="M10 10.2h574v400h-574zM12 12.2h570v396h-570zM60 10.2v2M110 10.2v2M160 10.2v2M210 10.2v2M260 10.2v2M310 10.2v2M360 10.2v2M410 10.2v2M460 10.2v2M510 10.2v2"/>
<path d="M536.5 11.8h.8M560 10.2v2M10 60.2h2M49 70.8h2.4v4.9l-1.2 .7-1.2-.7zM50.7 71.4v.7M74.4 70.8h2.4v4.9l-1.2 .7-1.2-.7zM99.8 70.8h2.4v4.9l-1.2 .7-1.2-.7zM125.2 70.8h2.4v4.9l-1.2 .7-1.2-.7zM126.5 71.3v.8l-.9-.3M150.6 70.8h2.4v4.9l-1.2 .7-1.2-.7zM176 70.8h2.4v4.9l-1.2 .7-1.2-.7zM201.4 70.8h2.4v4.9l-1.2 .7-1.2-.7z"/>
<path d="M203.1 71.8l-1.2-.5v.9M226.8 70.8h2.4v4.9l-1.2 .7-1.2-.7zM252.2 70.8h2.4v4.9l-1.2 .7-1.2-.7zM277.6 69.5h2.4v6.2l-1.2 .7-1.2-.7zM278.2 70.3a.61 .61 0 0 1 .7-.2 .61 .61 0 0 1 .4 .6 .76 .76 0 0 1-1.2-.2zM303 69.5h2.4v6.2l-1.2 .7-1.2-.7zM304.7 70.5h-1.2l.3 .4M304.7 70.1v.8M328.4 69.5h2.4v6.2l-1.2 .7-1.2-.7zM330.1 70.1v.8l-.9-.8-.3 .3 .1 .5M487 78.9h5.1M492.1 77.6h45.7v80h-45.7z"/>
<path d="M537.8 78.9h5.1M545.5 77.7h6.7v2.4h-6.7l-.7-1.2zM550.8 78.3l.5-.1 .3 .4-.8 .9h.8M582 60.2h2M35 82.2h5.6l.7 1.2-.7 1.1h-5.6zM56.5 94.8h12.7v12.7h-12.7zM61.6 86.5h2.5M62.9 86.5l1.2 2.6h-2.5zM62.9 84v7.6M62.9 92.2v2.6M81.9 94.8h12.7v12.7h-12.7zM87 86.5h2.5"/>
<path d="M88.3 86.5l1.2 2.6h-2.5zM88.3 84v7.6M88.3 92.2v2.6M107.3 94.8h12.7v12.7h-12.7zM112.4 86.5h2.5M113.7 86.5l1.2 2.6h-2.5zM113.7 84v7.6M113.7 92.2v2.6M132.7 94.8h12.7v12.7h-12.7zM137.8 86.5h2.5M139.1 86.5l1.2 2.6h-2.5zM139.1 84v7.6"/>
<path d="M139.1 92.2v2.6M158.1 94.8h12.7v12.7h-12.7zM163.2 86.5h2.5M164.5 86.5l1.2 2.6h-2.5zM164.5 84v7.6M164.5 92.2v2.6M183.5 94.8h12.7v12.7h-12.7zM188.6 86.5h2.5M189.9 86.5l1.2 2.6h-2.5zM189.9 84v7.6M189.9 92.2v2.6M208.9 94.8h12.7v12.7h-12.7z"/>
<path d="M214 86.5h2.5M215.3 86.5l1.2 2.6h-2.5zM215.3 84v7.6M215.3 92.2v2.6M234.3 94.8h12.7v12.7h-12.7zM239.4 86.5h2.5M240.7 86.5l1.2 2.6h-2.5zM240.7 84v7.6M240.7 92.2v2.6M259.7 94.8h12.7v12.7h-12.7zM264.8 86.5h2.5M266.1 86.5l1.2 2.6h-2.5z"/>
<path d="M266.1 84v7.6M266.1 92.2v2.6M285.1 94.8h12.7v12.7h-12.7zM290.2 86.5h2.5M291.5 86.5l1.2 2.6h-2.5zM291.5 84v7.6M291.5 92.2v2.6M310.5 94.8h12.7v12.7h-12.7zM315.6 86.5h2.5M316.9 86.5l1.2 2.6h-2.5zM316.9 84v7.6M316.9 92.2v2.6"/>
<path d="M335.9 94.8h12.7v12.7h-12.7zM341 86.5h2.5M342.3 86.5l1.2 2.6h-2.5zM342.3 84v7.6M342.3 92.2v2.6M388 95.4h2.5M394.3 94.2h5.4v2.4h-5.4l-.6-1.2zM471.2 96.7v2M471.2 99.7v2.1M476.2 96.7v2M476.2 99.7v2.1M477.2 85.3h4.8l.6 1.2-.6 1.2h-4.8z"/>
<path d="M487 86.5h5.1M487 82.7h5.1M487 90.3h5.1M487 94.1h5.1M537.8 95.4h5.1M537.8 86.5h5.1M537.8 91.6h5.1M537.8 89.1h5.1M537.8 84h5.1M537.8 81.4h5.1M537.8 98h5.1M544.8 87.9h9.3l.6 1.2-.6 1.2h-9.3z"/>
<path d="M545.5 90.4h5.6v2.4h-5.6l-.7-1.2zM545.5 85.3h6.2v2.4h-6.2l-.7-1.2zM545.5 80.3h6.7v2.3h-6.7l-.7-1.2zM545.5 82.8h6.7v2.4h-6.7l-.7-1.2zM545.5 94.2h6.7v2.4h-6.7l-.7-1.2zM545.5 96.8h6.7v2.4h-6.7l-.7-1.2zM550.3 86.2l.3-.4v1.3M550.3 87.1h.7M550.8 80.7h.8l-.5 .5 .4 .1v.6h-.7M550.8 97.2h.8l-.5 1.3M551.1 95.3l-.2-.5 .4-.1 .2 .4-.7 .4 .3 .5 .5-.3-.3-.4M551.1 83.2l-.3 .9h.8"/>
<path d="M551.4 83.7v.8M10 110.2h2M35 108.2h5.6l.7 1.2-.7 1.2h-5.6zM54 101.1h2.5M61.6 112.6h2.5M62.9 112.6l1.2 2.5h-2.5zM62.9 110v7.6M62.9 118.3v2.5M79.4 101.1h2.5M87 112.6h2.5M88.3 112.6l1.2 2.5h-2.5zM88.3 110v7.6"/>
<path d="M88.3 118.3v2.5M104.8 101.1h2.5M112.4 112.6h2.5M113.7 112.6l1.2 2.5h-2.5zM113.7 110v7.6M113.7 118.3v2.5M130.2 101.1h2.5M137.8 112.6h2.5M139.1 112.6l1.2 2.5h-2.5zM139.1 110v7.6M139.1 118.3v2.5M155.6 101.1h2.5"/>
<path d="M163.2 112.6h2.5M164.5 112.6l1.2 2.5h-2.5zM164.5 110v7.6M164.5 118.3v2.5M181 101.1h2.5M188.6 112.6h2.5M189.9 112.6l1.2 2.5h-2.5zM189.9 110v7.6M189.9 118.3v2.5M206.4 101.1h2.5M214 112.6h2.5M215.3 112.6l1.2 2.5h-2.5z"/>
<path d="M215.3 110v7.6M215.3 118.3v2.5M231.8 101.1h2.5M239.4 112.6h2.5M240.7 112.6l1.2 2.5h-2.5zM240.7 110v7.6M240.7 118.3v2.5M257.2 101.1h2.5M264.8 112.6h2.5M266.1 112.6l1.2 2.5h-2.5zM266.1 110v7.6M266.1 118.3v2.5"/>
<path d="M282.6 101.1h2.5M290.2 112.6h2.5M291.5 112.6l1.2 2.5h-2.5zM291.5 110v7.6M291.5 118.3v2.5M308 101.1h2.5M315.6 112.6h2.5M316.9 112.6l1.2 2.5h-2.5zM316.9 110v7.6M316.9 118.3v2.5M333.4 101.1h2.5M341 112.6h2.5"/>
<path d="M342.3 112.6l1.2 2.5h-2.5zM342.3 110v7.6M342.3 118.3v2.5M476.2 104.3v1.3h1.3l-1.3 1.2-1.2-1.2h1.2M478.2 114.5h6.9l.7 1.2-.7 1.2h-6.9zM478.6 112h6.5l.7 1.2-.7 1.2h-6.5zM481.6 104.4h3.5l.7 1.2-.7 1.2h-3.5l-.6-1.2zM481.6 101.8h3.5l.7 1.2-.7 1.2h-3.5l-.6-1.2zM482.3 102.3a.64 .64 0 0 1 .7 .7 .64 .64 0 0 1-.7 .6zM483.6 103.1h.9M487 103h5.1M487 105.6h5.1"/>
<path d="M487 113.2h5.1M487 115.7h5.1M537.8 109.4h5.1M537.8 106.8h5.1M537.8 104.3h5.1M537.8 113.2h5.1M537.8 115.7h5.1M537.8 101.8h5.1M537.8 118.3h5.1M545.5 100.6h5.6v2.4h-5.6l-.7-1.2zM545.5 119.6h5.6v2.4h-5.6l-.7-1.2zM545.5 114.5h5.1v2.4h-5.1l-.7-1.2z"/>
<path d="M545.5 112h5.3v2.4h-5.3l-.7-1.2zM545.5 105.7h4.2v2.3h-4.2l-.7-1.2zM545.5 103.1h4.2v2.4h-4.2l-.7-1.2zM545.5 108.2h6.7v2.4h-6.7l-.7-1.2zM545.5 117.1h6.7v2.4h-6.7l-.7-1.2zM550.8 109l.4-.3v1.2M550.8 109.9h.8M551.4 117.6l-.5 .3-.1 .7 .3 .2 .4-.1 .1-.4-.3-.2-.5 .2M582 110.2h2M35 134.2h5.6l.7 1.2-.7 1.2h-5.6zM54 127.2h2.5M56.5 120.8h12.7v12.7h-12.7z"/>
<path d="M61.6 138.6h2.5M62.9 138.6l1.2 2.5h-2.5zM62.9 136.1v7.6M79.4 127.2h2.5M81.9 120.8h12.7v12.7h-12.7zM87 138.6h2.5M88.3 138.6l1.2 2.5h-2.5zM88.3 136.1v7.6M104.8 127.2h2.5M107.3 120.8h12.7v12.7h-12.7zM112.4 138.6h2.5M113.7 138.6l1.2 2.5h-2.5z"/>
<path d="M113.7 136.1v7.6M130.2 127.2h2.5M132.7 120.8h12.7v12.7h-12.7zM137.8 138.6h2.5M139.1 138.6l1.2 2.5h-2.5zM139.1 136.1v7.6M155.6 127.2h2.5M158.1 120.8h12.7v12.7h-12.7zM163.2 138.6h2.5M164.5 138.6l1.2 2.5h-2.5zM164.5 136.1v7.6M181 127.2h2.5"/>
<path d="M183.5 120.8h12.7v12.7h-12.7zM188.6 138.6h2.5M189.9 138.6l1.2 2.5h-2.5zM189.9 136.1v7.6M206.4 127.2h2.5M208.9 120.8h12.7v12.7h-12.7zM214 138.6h2.5M215.3 138.6l1.2 2.5h-2.5zM215.3 136.1v7.6M231.8 127.2h2.5M234.3 120.8h12.7v12.7h-12.7zM239.4 138.6h2.5"/>
<path d="M240.7 138.6l1.2 2.5h-2.5zM240.7 136.1v7.6M257.2 127.2h2.5M259.7 120.8h12.7v12.7h-12.7zM264.8 138.6h2.5M266.1 138.6l1.2 2.5h-2.5zM266.1 136.1v7.6M282.6 127.2h2.5M285.1 120.8h12.7v12.7h-12.7zM290.2 138.6h2.5M291.5 138.6l1.2 2.5h-2.5zM291.5 136.1v7.6"/>
<path d="M308 127.2h2.5M310.5 120.8h12.7v12.7h-12.7zM315.6 138.6h2.5M316.9 138.6l1.2 2.5h-2.5zM316.9 136.1v7.6M333.4 127.2h2.5M335.9 120.8h12.7v12.7h-12.7zM341 138.6h2.5M342.3 138.6l1.2 2.5h-2.5zM342.3 136.1v7.6M478.9 128.5h6.2l.7 1.2-.7 1.2h-6.2zM478.9 131.1h6.2l.7 1.1-.7 1.2h-6.2z"/>
<path d="M479.7 137.4h5.4l.7 1.2-.7 1.2h-5.4zM480.2 120.9h4.9l.7 1.2-.7 1.2h-4.9zM480.2 123.4h4.9l.7 1.2-.7 1.2h-4.9zM487 138.6h5.1M487 122.1h5.1M487 124.6h5.1M487 129.7h5.1M487 132.2h5.1M537.8 139.9h5.1M537.8 137.3h5.1M537.8 134.8h5.1M537.8 131h5.1"/>
<path d="M537.8 128.4h5.1M537.8 125.9h5.1M537.8 123.4h5.1M537.8 120.8h5.1M545.5 133.6h9.6l.6 1.2-.6 1.2h-9.6zM545.5 124.7h5.6v2.4h-5.6l-.7-1.2zM545.5 127.2h6.2v2.4h-6.2l-.7-1.2zM545.5 138.7h4.9v2.4h-4.9l-.7-1.2zM545.5 136.1h4.9v2.4h-4.9l-.7-1.2zM545.5 122.2h6.7v2.4h-6.7l-.7-1.2zM549.8 121.4h.7M550.3 127.9l.5-.2 .2 .4-.8 .9h.8"/>
<path d="M551.5 122.6h-.6l-.1 .7h.7v.5h-.7M54 153.2h2.5M56.5 146.9h12.7v12.7h-12.7zM62.9 144.3v2.6M79.4 153.2h2.5M81.9 146.9h12.7v12.7h-12.7zM88.3 144.3v2.6M104.8 153.2h2.5M107.3 146.9h12.7v12.7h-12.7zM113.7 144.3v2.6M130.2 153.2h2.5M132.7 146.9h12.7v12.7h-12.7z"/>
<path d="M139.1 144.3v2.6M155.6 153.2h2.5M158.1 146.9h12.7v12.7h-12.7zM164.5 144.3v2.6M181 153.2h2.5M183.5 146.9h12.7v12.7h-12.7zM189.9 144.3v2.6M206.4 153.2h2.5M208.9 146.9h12.7v12.7h-12.7zM215.3 144.3v2.6M231.8 153.2h2.5M234.3 146.9h12.7v12.7h-12.7z"/>
<path d="M240.7 144.3v2.6M257.2 153.2h2.5M259.7 146.9h12.7v12.7h-12.7zM266.1 144.3v2.6M282.6 153.2h2.5M285.1 146.9h12.7v12.7h-12.7zM291.5 144.3v2.6M308 153.2h2.5M310.5 146.9h12.7v12.7h-12.7zM316.9 144.3v2.6M333.4 153.2h2.5M335.9 146.9h12.7v12.7h-12.7z"/>
<path d="M342.3 144.3v2.6M382.7 153.3h5.3l.6 1.2-.6 1.2h-5.3zM389.1 155.9h1.6v3.5h-1.6zM389.1 149.5h1.6v3.6h-1.6zM389.9 148.8v.7M389.9 153.1v.7M389.9 155.1v.8M389.9 159.4v.8M394.4 140.8h2.4v4.8l-1.2 .6-1.2-.6zM399.9 155.9h1.5v3.5h-1.5zM399.9 149.5h1.5v3.6h-1.5zM400.7 148.8v.7"/>
<path d="M400.7 153.1v.7M400.7 155.1v.8M400.7 159.4v.8M402.6 153.3h5.1v2.4h-5.1l-.6-1.2zM408.7 149.5h5.3l.7 1.2-.7 1.2h-5.3zM408.9 144.4h5.1l.7 1.2-.7 1.2h-5.1zM415.3 148.1v-1.2l-1.3 1.2 1.3 1.3v-1.3h5.1v1l.5 1.1M416.6 145.6h3.8v.5M419.1 158.9h10.2v10.2h-10.2zM419.1 143h10.2v10.2h-10.2zM420.4 150.2v.5h-3.8M420.9 146.1l-.5 1v1h-.5"/>
<path d="M423.5 146.3v3.6M423.8 145.4a2.74 2.74 0 0 1 2.7 2.8 2.74 2.74 0 0 1-2.7 2.7M423.8 146.3v3.6M424.1 146.3v3.6M424.3 150.5l-.6 .4 .7 .3M424.4 145.2l-.7 .3 .6 .3M427.6 148.1h.4M428 147.1v2M428.5 149.1v1.6h.8M429.3 145.6h-.8v1.5M433.7 149.5h6.5v2.4h-6.5l-.6-1.2zM433.7 144.4h6.5v2.4h-6.5l-.6-1.2z"/>
<path d="M478.4 141.2h6.7l.7 1.2-.7 1.2h-6.7zM487 142.4h5.1M487 156.4h5.1M487 151.3h5.1M487 153.8h5.1M487 148.8h5.1M537.8 152.6h5.1M537.8 150h5.1M537.8 147.5h5.1M537.8 144.9h5.1M537.8 142.4h5.1M537.8 156.4h5.1"/>
<path d="M545.5 155.2h4.9v2.4h-4.9l-.7-1.2zM545.5 141.2h4.9v2.4h-4.9l-.7-1.2zM545.5 148.8h6.2v2.4h-6.2l-.7-1.2zM545.5 151.4h4.9v2.4h-4.9l-.7-1.2zM545.5 146.3h4.9v2.4h-4.9l-.7-1.2zM545.5 143.8h4.9v2.3h-4.9l-.7-1.2zM549.1 156.9h.7M550.5 149.4l.1-.1a.62 .62 0 0 1 .5 .7 .62 .62 0 0 1-.6 .5l-.2-.4zM10 160.2h2M35 160.3h5.6l.7 1.2-.7 1.2h-5.6zM41.1 178h6.5l.7 1.2-.7 1.2h-6.5zM53.2 169.2h6.5l.6 1.1-.6 1.2h-6.5z"/>
<path d="M54 179.2h2.5M56.5 172.9h12.7v12.7h-12.7zM61.6 164.6h2.5M62.9 164.6l1.2 2.6h-2.5zM62.9 162.1v7.6M62.9 170.3v2.6M79.4 179.2h2.5M81.9 172.9h12.7v12.7h-12.7zM87 164.6h2.5M88.3 164.6l1.2 2.6h-2.5zM88.3 162.1v7.6M88.3 170.3v2.6"/>
<path d="M104.8 179.2h2.5M107.3 172.9h12.7v12.7h-12.7zM112.4 164.6h2.5M113.7 164.6l1.2 2.6h-2.5zM113.7 162.1v7.6M113.7 170.3v2.6M130.2 179.2h2.5M132.7 172.9h12.7v12.7h-12.7zM137.8 164.6h2.5M139.1 164.6l1.2 2.6h-2.5zM139.1 162.1v7.6M139.1 170.3v2.6"/>
<path d="M155.6 179.2h2.5M158.1 172.9h12.7v12.7h-12.7zM163.2 164.6h2.5M164.5 164.6l1.2 2.6h-2.5zM164.5 162.1v7.6M164.5 170.3v2.6M181 179.2h2.5M183.5 172.9h12.7v12.7h-12.7zM188.6 164.6h2.5M189.9 164.6l1.2 2.6h-2.5zM189.9 162.1v7.6M189.9 170.3v2.6"/>
<path d="M206.4 179.2h2.5M208.9 172.9h12.7v12.7h-12.7zM214 164.6h2.5M215.3 164.6l1.2 2.6h-2.5zM215.3 162.1v7.6M215.3 170.3v2.6M231.8 179.2h2.5M234.3 172.9h12.7v12.7h-12.7zM239.4 164.6h2.5M240.7 164.6l1.2 2.6h-2.5zM240.7 162.1v7.6M240.7 170.3v2.6"/>
<path d="M257.2 179.2h2.5M259.7 172.9h12.7v12.7h-12.7zM264.8 164.6h2.5M266.1 164.6l1.2 2.6h-2.5zM266.1 162.1v7.6M266.1 170.3v2.6M282.6 179.2h2.5M285.1 172.9h12.7v12.7h-12.7zM290.2 164.6h2.5M291.5 164.6l1.2 2.6h-2.5zM291.5 162.1v7.6M291.5 170.3v2.6"/>
<path d="M308 179.2h2.5M310.5 172.9h12.7v12.7h-12.7zM315.6 164.6h2.5M316.9 164.6l1.2 2.6h-2.5zM316.9 162.1v7.6M316.9 170.3v2.6M333.4 179.2h2.5M335.9 172.9h12.7v12.7h-12.7zM341 164.6h2.5M342.3 164.6l1.2 2.6h-2.5zM342.3 162.1v7.6M342.3 170.3v2.6"/>
<path d="M345.4 168.5h6.5v2.4h-6.5l-.6-1.2zM389.9 167.8v1.3h1.3l-1.3 1.2-1.3-1.2h1.3M389.9 162.1v2M389.9 165.1v2.1M400.7 167.8v1.3h1.3l-1.3 1.2-1.3-1.2h1.3M400.7 162.1v2M400.7 165.1v2.1M408.7 165.3h5.3l.7 1.2-.7 1.2h-5.3zM408.9 160.3h5.1l.7 1.2-.7 1.2h-5.1zM415.3 164v-1.3l-1.3 1.3 1.3 1.3v-1.3h5.1v1l.5 1M416.6 161.5h3.8v.5M420.4 166v.5h-3.8"/>
<path d="M420.9 162l-.5 1v1h-.5M423.5 162.2v3.6M423.8 161.3a2.74 2.74 0 0 1 2.7 2.8 2.74 2.74 0 0 1-2.7 2.7M423.8 162.2v3.6M424.1 162.2v3.6M424.3 166.4l-.6 .4 .7 .2M424.4 161.1l-.7 .2 .6 .4M427.6 164h.4M428 163v2M428.5 165v1.5h.8M429.3 161.5h-.8v1.5M433.7 165.3h6.5v2.4h-6.5l-.6-1.2z"/>
<path d="M433.7 160.3h6.5v2.4h-6.5l-.6-1.2zM438.8 162h.8M485.1 160.2v1.3h1.3l-1.3 1.2-1.2-1.2h1.2M505.5 171.8h2.4v6.2l-1.2 .6-1.2-.6zM513.1 177.6v-1.3h5.1v1.3M513.1 179.9h.5M515.6 171h1.3l-1.3-1.3-1.3 1.3h1.3v1.3M517.7 179.9h.5M523.3 171.8h2.4v6.2l-1.2 .6-1.2-.6zM582 160.2h2M155.6 198.3h2.5M158.1 191.9h12.7v12.7h-12.7z"/>
<path d="M164.5 189.4v2.5M181 198.3h2.5M183.5 191.9h12.7v12.7h-12.7zM189.9 189.4v2.5M206.4 198.3h2.5M208.9 191.9h12.7v12.7h-12.7zM215.3 189.4v2.5M328.4 181.1l1.2-.6 1.2 .6v6.5h-2.4zM398.8 195.1v-1.3l-1.3 1.3 1.3 1.3v-1.3h1.2M401.3 195.1h2.6M404.1 194.8a3.2 3.2 0 0 1 3.5-.7 3.2 3.2 0 0 1 2 2.9v1.9a3.2 3.2 0 0 1-3.2 3.2 3.2 3.2 0 0 1-3.2-3.2v-1.9a3 3 0 0 1 .9-2.2zM406.4 197.7v1.9l.5 .1-1 .2 1 .3-1 .2 1 .3-1 .3 .5 .1v2.9"/>
<path d="M406.7 197.7l-2.6-2.6v3.8h.4l.1 .5 .3-1 .2 1 .3-1 .2 1 .3-1 .1 .5h.4M411.5 195.1h-2.8l-2.6 2.6M422.9 186.2h1.3l-1.3-1.2-1.3 1.2h1.3v1.3M422.9 188.8v2M422.9 191.8v2M431.2 193.9h5.4l.7 1.2-.7 1.2h-5.4l-.7-1.2zM506.7 182.4v2M506.7 185.5v2M513.1 182.2v1.2h5.1v-1.2M515.6 188.8v1.2h1.3l-1.3 1.3-1.3-1.3h1.3M524.5 182.4v2M524.5 185.5v2"/>
<path d="M10 210.2h2M388.9 209.2h4.8l.6 1.2-.6 1.1h-4.8zM394.3 210.4h2.6M396.9 209.1h5.1M399.4 207.3v1.8M402 210.4h2.5M408.3 210.4h7.6M410.8 209.1l2.6 1.3-2.6 1.2zM413.4 209.1v2.5M418.3 213.7h1.6v3.5h-1.6zM419.1 219.2v1.3h1.3l-1.3 1.3-1.3-1.3h1.3M419.1 212.9v.8"/>
<path d="M419.1 217.2v.8M422.9 219.2v1.3h1.3l-1.3 1.3-1.3-1.3h1.3M422.9 212.9v2M422.9 215.9v2.1M431.2 209.2h6.7l.7 1.2-.7 1.1h-6.7l-.7-1.1zM582 210.2h2M334.2 238.9h4.3M340.4 238.9h1.2v-1.2l1.3 1.2-1.3 1.3v-1.3M417.8 238.3h7.6M420.4 238.3l2.5-1.3v2.6zM420.4 237v2.6M67.4 253.1h2.4v3l-1.2 .6-1.2-.6z"/>
<path d="M73 259.2v.8M80 259.2v.8M87 259.2v.8M94 259.2v.8M101 259.2v.8M107.9 259.2v.8M114.9 259.2v.8M121.9 259.2v.8M128.9 259.2v.8M135.9 259.2v.8M142.9 259.2v.8M149.9 259.2v.8"/>
<path d="M208.9 243.4h20.3v63.5h-20.3zM228.2 258.4h1v.5h-1zM228.2 253.3h1v.5h-1zM228.2 250.7h1v.5h-1zM228.2 245.7h1v.5h-1zM229.2 245.9h5.1M229.2 251h5.1M229.2 258.6h5.1M229.2 253.5h5.1M239.4 257.4h7l.6 1.2-.6 1.2h-7l-.6-1.2zM240 251h.8M240.8 250.2h3.5v1.6h-3.5z"/>
<path d="M244.3 251h.8M245.7 258.4l-.5 .1 .5 .3v.3h-.5M245.7 244.7h5.6l.7 1.2-.7 1.2h-5.6zM246.4 251h1.2v-1.3l1.3 1.3-1.3 1.3v-1.3M284.1 249.7h4.2M284.1 247.2h4.2M284.1 244.6h4.2M284.1 242.1h4.2M290.2 249.7h1.3v-1.2l1.2 1.2-1.2 1.3v-1.3M290.8 240.9h3v2.4h-3l-.6-1.2zM290.8 243.5h4.3v2.3h-4.3l-.6-1.2zM290.8 246h4.2v2.4h-4.2l-.6-1.2z"/>
<path d="M334.2 251.6h4.3M334.2 249.1h4.3M334.2 246.5h4.3M334.2 244h4.3M334.2 241.5h4.3M341 247.9h6.9v2.4h-6.9l-.6-1.2zM341 245.4h6.5v2.3h-6.5l-.6-1.2zM341 250.4h4.8v2.4h-4.8l-.6-1.2zM341 242.8h6.8v2.4h-6.8l-.6-1.2zM341 240.3h5.5v2.4h-5.5l-.6-1.2zM390.7 249.2h5.5l.7 1.2-.7 1.2h-5.5zM398.1 250.4h5.1"/>
<path d="M399.4 249.9h2.6v1h-2.6zM402 249.3h-.6l-1.5 2.1h-.5M405.8 245.5l1.2-.7 1.2 .7v3h-2.4zM407 253.4l1.1 1.5h-2.1zM407 258v1.2h1.3l-1.3 1.3-1.2-1.3h1.2M407 251.6v5.1M407.8 253.2h.3v.2h-2.1v.3h.3M412.7 256.7v2M412.7 259.8v2M414 250.4h2.6M416.6 248.5h10.1v6.9h-10.1zM421.6 255.4v2.6"/>
<path d="M426.7 250.4h2.6M430.5 257.3v2.1M438.1 249.2h4.9l.6 1.2-.6 1.2h-4.9zM492.8 256.7v2M492.8 259.8v2M501.6 256.7v2M501.6 259.8v2M509.3 247.5l1.2-.7 1.2 .7v4.8l-1.2 .6-1.2-.6zM510.5 256.7v2M510.5 259.8v2M519.4 256.7v2M519.4 259.8v2"/>
<path d="M528.3 256.7v2M528.3 259.8v2M10 260.2h2M71.8 269.4h2.5M72.3 260h1.5v3.6h-1.5zM72.3 277.2h1.5v3.5h-1.5zM73 263.6v3.3h1.3h-2.5l1.2 2.5 1.3-2.5h-1.3M73 269.4v2.5M73 276.4v.8M78.7 269.4h2.6M79.2 260h1.6v3.6h-1.6zM79.2 277.2h1.6v3.5h-1.6z"/>
<path d="M80 263.6v3.3h1.3h-2.6l1.3 2.5 1.3-2.5h-1.3M80 269.4v2.5M80 276.4v.8M85.7 269.4h2.6M86.2 260h1.6v3.6h-1.6zM86.2 277.2h1.6v3.5h-1.6zM87 263.6v3.3h1.3h-2.6l1.3 2.5 1.3-2.5h-1.3M87 269.4v2.5M87 276.4v.8M92.7 269.4h2.5M93.2 260h1.5v3.6h-1.5zM93.2 277.2h1.5v3.5h-1.5z"/>
<path d="M94 263.6v3.3h1.2h-2.5l1.3 2.5 1.2-2.5h-1.2M94 269.4v2.5M94 276.4v.8M99.7 269.4h2.5M100.2 260h1.5v3.6h-1.5zM100.2 277.2h1.5v3.5h-1.5zM101 263.6v3.3h1.2h-2.5l1.3 2.5 1.2-2.5h-1.2M101 269.4v2.5M101 276.4v.8M106.7 269.4h2.5M107.2 260h1.5v3.6h-1.5zM107.2 277.2h1.5v3.5h-1.5z"/>
<path d="M107.9 263.6v3.3h1.3h-2.5l1.2 2.5 1.3-2.5h-1.3M107.9 269.4v2.5M107.9 276.4v.8M113.7 269.4h2.5M114.2 260h1.5v3.6h-1.5zM114.2 277.2h1.5v3.5h-1.5zM114.9 263.6v3.3h1.3h-2.5l1.2 2.5 1.3-2.5h-1.3M114.9 269.4v2.5M114.9 276.4v.8M120.6 269.4h2.6M121.2 260h1.5v3.6h-1.5zM121.2 277.2h1.5v3.5h-1.5z"/>
<path d="M121.9 263.6v3.3h1.3h-2.6l1.3 2.5 1.3-2.5h-1.3M121.9 269.4v2.5M121.9 276.4v.8M127.6 269.4h2.6M128.1 260h1.6v3.6h-1.6zM128.1 277.2h1.6v3.5h-1.6zM128.9 263.6v3.3h1.3h-2.6l1.3 2.5 1.3-2.5h-1.3M128.9 269.4v2.5M128.9 276.4v.8M134.6 269.4h2.6M135.1 260h1.6v3.6h-1.6zM135.1 277.2h1.6v3.5h-1.6z"/>
<path d="M135.9 263.6v3.3h1.3h-2.6l1.3 2.5 1.3-2.5h-1.3M135.9 269.4v2.5M135.9 276.4v.8M141.6 269.4h2.5M142.1 260h1.5v3.6h-1.5zM142.1 277.2h1.5v3.5h-1.5zM142.9 263.6v3.3h1.2h-2.5l1.3 2.5 1.2-2.5h-1.2M142.9 269.4v2.5M142.9 276.4v.8M148.6 269.4h2.5M149.1 260h1.5v3.6h-1.5zM149.1 277.2h1.5v3.5h-1.5z"/>
<path d="M149.9 263.6v3.3h1.2h-2.5l1.3 2.5 1.2-2.5h-1.2M149.9 269.4v2.5M149.9 276.4v.8M211.5 275.1l.1 .5 .4 .2 .5-.2 .2-.5M211.5 267.5l.1-.5 .4-.1 .5 .1 .2 .5M228.2 278.7h1v.5h-1zM228.2 273.6h1v.5h-1zM228.2 271.1h1v.5h-1zM228.2 266h1v.5h-1zM228.2 263.4h1v.5h-1zM228.2 260.9h1v.5h-1zM229.2 278.9h5.1"/>
<path d="M229.2 263.7h5.1M229.2 271.3h5.1M229.2 273.9h5.1M229.2 266.2h5.1M229.2 261.2h5.1M239.4 262.5h7l.6 1.2-.6 1.2h-7l-.6-1.2zM240.7 266.2h.7M241.4 265.5h3.6v1.5h-3.6zM245 266.2h.7M245.7 263.5l-.5 .1 .5 .3v.3h-.5M247.6 265h5.6l.7 1.2-.7 1.2h-5.6zM284.1 278.3h4.2"/>
<path d="M284.1 275.8h4.2M284.1 273.2h4.2M284.1 270.7h4.2M290.8 269.5h6.8v2.4h-6.8l-.6-1.2zM290.8 272h6.8v2.4h-6.8l-.6-1.2zM290.8 274.6h6.8v2.4h-6.8l-.6-1.2zM290.8 277.1h6.8v2.4h-6.8l-.6-1.2zM296.1 275h.8l-.4 .5 .4 .2v.5h-.8M296.2 270.3l.4-.3v1.2M296.2 272.6l.5-.1 .2 .4-.8 .9h.8M296.2 271.2h.7M296.5 277.5l-.3 .9h.8"/>
<path d="M296.8 278v.9M334.2 278.3h4.3M334.2 275.8h4.3M334.2 273.2h4.3M334.2 270.7h4.3M341 269.5h6.7v2.4h-6.7l-.6-1.2zM341 272h6.7v2.4h-6.7l-.6-1.2zM341 274.6h6.7v2.4h-6.7l-.6-1.2zM341 277.1h6.7v2.4h-6.7l-.6-1.2zM346.3 275h.8l-.5 1.3M346.6 278.1l-.2-.4 .5-.1 .1 .4-.6 .4 .2 .5 .5-.3-.2-.5M347 272.5l-.6 .3v.7l.2 .3 .4-.1 .1-.5-.2-.2-.5 .2"/>
<path d="M347 270h-.6v.6h.6v.5h-.6M421.6 267.5v1.3h1.3l-1.3 1.2-1.2-1.2h1.2M430.5 260.4v2M510.5 265v1.2h1.3l-1.3 1.3-1.2-1.3h1.2M582 260.2h2M71.8 287.8h2.5M72.3 294.9h1.5v3.6h-1.5zM73 282.7v2.6h1.3h-2.5l1.2 2.5 1.3-2.5h-1.3M73 280.7v.8M73 287.8v2.6M73 294.2v.7M73 298.5v.8"/>
<path d="M78.7 287.8h2.6M79.2 294.9h1.6v3.6h-1.6zM80 282.7v2.6h1.3h-2.6l1.3 2.5 1.3-2.5h-1.3M80 280.7v.8M80 287.8v2.6M80 294.2v.7M80 298.5v.8M85.7 287.8h2.6M86.2 294.9h1.6v3.6h-1.6zM87 282.7v2.6h1.3h-2.6l1.3 2.5 1.3-2.5h-1.3M87 280.7v.8M87 287.8v2.6"/>
<path d="M87 294.2v.7M87 298.5v.8M92.7 287.8h2.5M93.2 294.9h1.5v3.6h-1.5zM94 282.7v2.6h1.2h-2.5l1.3 2.5 1.2-2.5h-1.2M94 280.7v.8M94 287.8v2.6M94 294.2v.7M94 298.5v.8M99.7 287.8h2.5M100.2 294.9h1.5v3.6h-1.5zM101 282.7v2.6h1.2h-2.5l1.3 2.5 1.2-2.5h-1.2"/>
<path d="M101 280.7v.8M101 287.8v2.6M101 294.2v.7M101 298.5v.8M106.7 287.8h2.5M107.2 294.9h1.5v3.6h-1.5zM107.9 282.7v2.6h1.3h-2.5l1.2 2.5 1.3-2.5h-1.3M107.9 280.7v.8M107.9 287.8v2.6M107.9 294.2v.7M107.9 298.5v.8M113.7 287.8h2.5"/>
<path d="M114.2 294.9h1.5v3.6h-1.5zM114.9 282.7v2.6h1.3h-2.5l1.2 2.5 1.3-2.5h-1.3M114.9 280.7v.8M114.9 287.8v2.6M114.9 294.2v.7M114.9 298.5v.8M120.6 287.8h2.6M121.2 294.9h1.5v3.6h-1.5zM121.9 282.7v2.6h1.3h-2.6l1.3 2.5 1.3-2.5h-1.3M121.9 280.7v.8M121.9 287.8v2.6M121.9 294.2v.7"/>
<path d="M121.9 298.5v.8M127.6 287.8h2.6M128.1 294.9h1.6v3.6h-1.6zM128.9 282.7v2.6h1.3h-2.6l1.3 2.5 1.3-2.5h-1.3M128.9 280.7v.8M128.9 287.8v2.6M128.9 294.2v.7M128.9 298.5v.8M134.6 287.8h2.6M135.1 294.9h1.6v3.6h-1.6zM135.9 282.7v2.6h1.3h-2.6l1.3 2.5 1.3-2.5h-1.3M135.9 280.7v.8"/>
<path d="M135.9 287.8v2.6M135.9 294.2v.7M135.9 298.5v.8M141.6 287.8h2.5M142.1 294.9h1.5v3.6h-1.5zM142.9 282.7v2.6h1.2h-2.5l1.3 2.5 1.2-2.5h-1.2M142.9 280.7v.8M142.9 287.8v2.6M142.9 294.2v.7M142.9 298.5v.8M148.6 287.8h2.5M149.1 294.9h1.5v3.6h-1.5z"/>
<path d="M149.9 282.7v2.6h1.2h-2.5l1.3 2.5 1.2-2.5h-1.2M149.9 280.7v.8M149.9 287.8v2.6M149.9 294.2v.7M149.9 298.5v.8M228.2 296.5h1v.5h-1zM228.2 293.9h1v.5h-1zM228.2 288.8h1v.5h-1zM228.2 286.3h1v.5h-1zM228.2 281.2h1v.5h-1zM229.2 286.6h5.1M229.2 289.1h5.1"/>
<path d="M229.2 281.5h5.1M229.2 296.7h5.1M229.2 294.2h5.1M292.2 296.3h2.4v3l-1.2 .6-1.2-.6zM10 310.2h2M71.8 305.6h2.5M72.3 312.1h1.5v3.5h-1.5zM73 300.5v2.6h1.3h-2.5l1.2 2.5 1.3-2.5h-1.3M73 317.7v2.5h1.3h-2.5l1.2 2.5 1.3-2.5h-1.3M73 305.6v2.5M73 311.3v.8M73 315.6v.8"/>
<path d="M78.7 305.6h2.6M79.2 312.1h1.6v3.5h-1.6zM80 300.5v2.6h1.3h-2.6l1.3 2.5 1.3-2.5h-1.3M80 317.7v2.5h1.3h-2.6l1.3 2.5 1.3-2.5h-1.3M80 305.6v2.5M80 311.3v.8M80 315.6v.8M85.7 305.6h2.6M86.2 312.1h1.6v3.5h-1.6zM87 300.5v2.6h1.3h-2.6l1.3 2.5 1.3-2.5h-1.3M87 317.7v2.5h1.3h-2.6l1.3 2.5 1.3-2.5h-1.3M87 305.6v2.5"/>
<path d="M87 311.3v.8M87 315.6v.8M92.7 305.6h2.5M93.2 312.1h1.5v3.5h-1.5zM94 300.5v2.6h1.2h-2.5l1.3 2.5 1.2-2.5h-1.2M94 317.7v2.5h1.2h-2.5l1.3 2.5 1.2-2.5h-1.2M94 305.6v2.5M94 311.3v.8M94 315.6v.8M99.7 305.6h2.5M100.2 312.1h1.5v3.5h-1.5zM101 300.5v2.6h1.2h-2.5l1.3 2.5 1.2-2.5h-1.2"/>
<path d="M101 317.7v2.5h1.2h-2.5l1.3 2.5 1.2-2.5h-1.2M101 305.6v2.5M101 311.3v.8M101 315.6v.8M103.5 317.7v2.5h1.3h-2.6l1.3 2.5 1.3-2.5h-1.3M106.7 305.6h2.5M107.2 312.1h1.5v3.5h-1.5zM107.9 300.5v2.6h1.3h-2.5l1.2 2.5 1.3-2.5h-1.3M107.9 317.7v2.5h1.3h-2.5l1.2 2.5 1.3-2.5h-1.3M107.9 305.6v2.5M107.9 311.3v.8M107.9 315.6v.8"/>
<path d="M110.5 317.7v2.5h1.3h-2.6l1.3 2.5 1.3-2.5h-1.3M113.7 305.6h2.5M114.2 312.1h1.5v3.5h-1.5zM114.9 300.5v2.6h1.3h-2.5l1.2 2.5 1.3-2.5h-1.3M114.9 317.7v2.5h1.3h-2.5l1.2 2.5 1.3-2.5h-1.3M114.9 305.6v2.5M114.9 311.3v.8M114.9 315.6v.8M117.5 317.7v2.5h1.2h-2.5l1.3 2.5 1.2-2.5h-1.2M120.6 305.6h2.6M121.2 312.1h1.5v3.5h-1.5zM121.9 300.5v2.6h1.3h-2.6l1.3 2.5 1.3-2.5h-1.3"/>
<path d="M121.9 317.7v2.5h1.3h-2.6l1.3 2.5 1.3-2.5h-1.3M121.9 305.6v2.5M121.9 311.3v.8M121.9 315.6v.8M127.6 305.6h2.6M128.1 312.1h1.6v3.5h-1.6zM128.9 300.5v2.6h1.3h-2.6l1.3 2.5 1.3-2.5h-1.3M128.9 317.7v2.5h1.3h-2.6l1.3 2.5 1.3-2.5h-1.3M128.9 305.6v2.5M128.9 311.3v.8M128.9 315.6v.8M134.6 305.6h2.6"/>
<path d="M135.1 312.1h1.6v3.5h-1.6zM135.9 300.5v2.6h1.3h-2.6l1.3 2.5 1.3-2.5h-1.3M135.9 317.7v2.5h1.3h-2.6l1.3 2.5 1.3-2.5h-1.3M135.9 305.6v2.5M135.9 311.3v.8M135.9 315.6v.8M141.6 305.6h2.5M142.1 312.1h1.5v3.5h-1.5zM142.9 300.5v2.6h1.2h-2.5l1.3 2.5 1.2-2.5h-1.2M142.9 317.7v2.5h1.2h-2.5l1.3 2.5 1.2-2.5h-1.2M142.9 305.6v2.5M142.9 311.3v.8"/>
<path d="M142.9 315.6v.8M148.6 305.6h2.5M149.1 312.1h1.5v3.5h-1.5zM149.9 300.5v2.6h1.2h-2.5l1.3 2.5 1.2-2.5h-1.2M149.9 317.7v2.5h1.2h-2.5l1.3 2.5 1.2-2.5h-1.2M149.9 305.6v2.5M149.9 311.3v.8M149.9 315.6v.8M205.4 314.5h2v5.1h-2zM206.4 313.2v1.3M206.4 319.6v1.2M211.5 306.9v5.1"/>
<path d="M211.5 314.5v2M211.5 317.5v2.1M218.8 305.9h.5v1h-.5zM219.1 306.9v6.3h1.2l-1.2 1.3-1.3-1.3h1.3M228.2 304.1h1v.5h-1zM228.2 301.5h1v.5h-1zM229.2 301.8h5.1M229.2 304.3h5.1M274.2 309.5h9.6l.7 1.2-.7 1.2h-9.6zM285.7 310.7h2.6M288.3 305.6h10.1v10.2h-10.1zM293.4 303.1v2.5"/>
<path d="M293.4 315.8v2.5M294.6 313.2h.5M295.7 313.2l-1.1 1v-.5M295.7 312.2l-1.1 1v-.5M296 312.2h2.1l-1 2zM296 314.2h2.1M297.1 311.7v3M298.4 310.7h2.6M302.3 310.7h2.5M304.8 305.6h10.2v10.2h-10.2zM309.9 303.1v2.5M309.9 315.8v2.5"/>
<path d="M311.1 313.2h.6M312.2 313.2l-1.1 1v-.5M312.2 312.2l-1.1 1v-.5M312.5 312.2h2.1l-1 2zM312.5 314.2h2.1M313.6 311.7v3M315 310.7h2.5M318.8 310.7h2.5M321.3 305.6h10.2v10.2h-10.2zM326.4 303.1v2.5M326.4 315.8v2.5M327.7 313.2h.5"/>
<path d="M328.7 313.2l-1 1v-.5M328.7 312.2l-1 1v-.5M329.1 312.2h2l-1 2zM329.1 314.2h2M330.1 311.7v3M331.5 310.7h2.5M335.3 310.7h2.5M337.8 305.6h10.2v10.2h-10.2zM342.9 303.1v2.5M342.9 315.8v2.5M344.2 313.2h.5M345.2 313.2l-1 1v-.5"/>
<path d="M345.2 312.2l-1 1v-.5M345.6 312.2h2l-1 2zM345.6 314.2h2M346.6 311.7v3M348 310.7h2.5M391.2 305.7h6.9l.7 1.2-.7 1.2h-6.9l-.7-1.2zM391.8 306.2a.64 .64 0 0 1 .8 .6 .64 .64 0 0 1-.8 .6zM396.2 313.9h15.3v15.2h-15.3zM397.5 318.9h12.7v5.1h-12.7zM399 317.9l2.1 1-2.1 1.1zM401.1 317.9v2.1M401.3 308.8v7.6h2.6"/>
<path d="M406.4 308.8v7.6h-2.5v2.5M406.7 317.9l2 1-2 1.1zM407.7 306.9h.7M408.4 306.1h3.6v1.5h-3.6zM408.7 317.9v2.1M412 306.9h.7M414.7 305.7h3.5l.6 1.2-.6 1.2h-3.5l-.7-1.2zM415.2 306.2a.64 .64 0 0 1 .8 .6 .64 .64 0 0 1-.8 .6zM416.5 307h1M458.1 308.1h2v5.1h-2zM459.1 315.8v1.2h1.3l-1.3 1.3-1.3-1.3h1.3M459.1 306.9v1.2"/>
<path d="M459.1 313.2v1.3M464.2 308.1v2.1M464.2 311.2v2M466.7 306.9h7.6M469.3 306.9l2.5-1.3v2.5zM469.3 305.6v2.5M475.6 305.7h5.4v2.4h-5.4l-.6-1.2zM582 310.2h2M46.6 329.2h9.3l.6 1.2-.6 1.2h-9.3zM58.4 330.4h.8M59.2 329.6h3.5v1.5h-3.5zM62.7 330.4h.8"/>
<path d="M64 333h1.5v3.6h-1.5zM64.8 332.3v.7M64.8 336.6v.8M65.4 330.4h5.3M70.7 328.5v3.8M71.2 332.1h1.8M71.2 328.1v1M71.2 331.6v1.1M71.2 328.6h1.8M71.8 322.7h2.5M73 328.6h.8v3.5h-.8M73 322.7v5.9"/>
<path d="M73 332.1v3.3M78.7 322.7h2.6M80 322.7v2.6M85.7 322.7h2.6M87 322.7v2.6M92.7 322.7h2.5M94 322.7v2.6M99.7 322.7h5.1M101 322.7v2.6M103.5 322.7v2.6M106.7 322.7h5.1M107.9 322.7v2.6"/>
<path d="M110.5 322.7v2.6M113.7 322.7h5M114.9 322.7v2.6M117.5 322.7v2.6M120.6 322.7h2.6M121.9 322.7v2.6M127.6 322.7h2.6M128.9 322.7v2.6M134.6 322.7h2.6M135.9 322.7v2.6M141.6 322.7h2.5M142.9 322.7v2.6"/>
<path d="M148.6 322.7h2.5M149.9 322.7v2.6M206.4 322.1v1.3h1.2l-1.2 1.3-1.3-1.3h1.3M274.2 333h9.6l.7 1.2-.7 1.2h-9.6zM285.7 334.2h2.6M288.3 329.1h10.1v10.2h-10.1zM292.2 320.4h2.4v3l-1.2 .6-1.2-.6zM293.4 326.6v2.5M293.4 339.3v2.5M294.6 336.7h.5M295.7 336.7l-1.1 1v-.5M295.7 335.7l-1.1 1v-.5"/>
<path d="M296 335.7h2.1l-1 2zM296 337.7h2.1M297.1 335.2v3M298.4 334.2h2.6M302.3 334.2h2.5M304.8 329.1h10.2v10.2h-10.2zM309.9 320.8v1.3h1.2l-1.2 1.3-1.3-1.3h1.3M309.9 326.6v2.5M309.9 339.3v2.5M311.1 336.7h.6M312.2 336.7l-1.1 1v-.5M312.2 335.7l-1.1 1v-.5"/>
<path d="M312.5 335.7h2.1l-1 2zM312.5 337.7h2.1M313.6 335.2v3M315 334.2h2.5M318.8 334.2h2.5M321.3 329.1h10.2v10.2h-10.2zM326.4 326.6v2.5M326.4 339.3v2.5M327.7 336.7h.5M328.7 336.7l-1 1v-.5M328.7 335.7l-1 1v-.5M329.1 335.7h2l-1 2z"/>
<path d="M329.1 337.7h2M330.1 335.2v3M331.5 334.2h2.5M335.3 334.2h2.5M337.8 329.1h10.2v10.2h-10.2zM342.9 326.6v2.5M342.9 339.3v2.5M344.2 336.7h.5M345.2 336.7l-1 1v-.5M345.2 335.7l-1 1v-.5M345.6 335.7h2l-1 2zM345.6 337.7h2"/>
<path d="M346.6 335.2v3M348 334.2h2.5M387.3 321.5v-1.3l-1.2 1.3 1.2 1.2v-1.2h1.3M391.2 334.3h6.9l.7 1.1-.7 1.2h-6.9l-.7-1.2zM391.2 321.5h25.4M399 323l2.1 1-2.1 1zM401.1 323v2M402.8 320.5l2.1 1-2.1 1zM403.9 324v2.6h2.5v7.6M403.9 326.6h-2.6v7.6M404.4 320.5h.5v2M406.7 323l2 1-2 1z"/>
<path d="M407.7 335.4h.7M408.4 334.7h3.6v1.5h-3.6zM408.7 323v2M412 335.4h.7M414.7 334.3h3.5l.6 1.1-.6 1.2h-3.5l-.7-1.2zM417.8 331.6v1.3h1.3l-1.3 1.3-1.2-1.3h1.2M417.8 324v2.1M417.8 327.1v2M73 342.4v1.3h1.3l-1.3 1.3-1.2-1.3h1.2M309.9 344.3v1.3h1.2l-1.2 1.3-1.3-1.3h1.3M10 360.2h2M474 376.2h108v32h-108z"/>
<path d="M582 360.2h2M474 397.7h108M474 391.7h108M484.6 392.2l-1.3 2M490 395.6l-.4-.1-.3 .3v.6h.7M490.6 395.6h.6l.1 .9M490.6 395v1.5M60 408.2v2M110 408.2v2M160 408.2v2M210 408.2v2M260 408.2v2"/>
<path d="M310 408.2v2M360 408.2v2M410 408.2v2M460 408.2v2M474 404.7h108M474 401.7h108M483.1 402.6l.6-.2 .3 .5-.9 1h.9M494 401.7v3M499.3 405.2h-.7v.7h.7v.7h-.7M500 406.6v.1M500.7 405.7l.4-.5v1.5M500.7 406.7h.8"/>
<path d="M502.2 406.6v.1M502.8 405.4l.6-.2 .3 .5-.9 1h.9M510 408.2v2M514 402.4h-.7l-.1 .7h.7l.1 .7h-.8M514.7 403.4h1.1M516.5 402.6l.5-.2 .3 .5-.9 1h.9M517.9 402.6l.6-.2 .3 .5-1 1h1M536.5 409.7h.8M558 401.7v6.5M560 408.2v2M566.8 405.1l-1.2 2M567.3 405.7l.4-.5v1.5"/>
<path d="M567.3 406.7h.8"/>
<circle cx="423.8" cy="148.1" r="1.91"/>
<circle cx="428.5" cy="149.1" r=".13"/>
<circle cx="428.5" cy="147.1" r=".13"/>
<circle cx="423.8" cy="164" r="1.91"/>
<circle cx="428.5" cy="165" r=".13"/>
<circle cx="428.5" cy="163" r=".13"/>
<circle cx="404.1" cy="195.1" r=".13"/>
<circle cx="406.4" cy="198.9" r=".13"/>
<circle cx="397.4" cy="210.4" r=".51"/>
<circle cx="401.4" cy="210.4" r=".51"/>
<circle cx="73" cy="268.1" r="2.84"/>
<circle cx="80" cy="268.1" r="2.84"/>
<circle cx="87" cy="268.1" r="2.84"/>
<circle cx="94" cy="268.1" r="2.84"/>
<circle cx="101" cy="268.1" r="2.84"/>
<circle cx="107.9" cy="268.1" r="2.84"/>
<circle cx="114.9" cy="268.1" r="2.84"/>
<circle cx="121.9" cy="268.1" r="2.84"/>
<circle cx="128.9" cy="268.1" r="2.84"/>
<circle cx="135.9" cy="268.1" r="2.84"/>
<circle cx="142.9" cy="268.1" r="2.84"/>
<circle cx="149.9" cy="268.1" r="2.84"/>
<circle cx="73" cy="286.6" r="2.84"/>
<circle cx="80" cy="286.6" r="2.84"/>
<circle cx="87" cy="286.6" r="2.84"/>
<circle cx="94" cy="286.6" r="2.84"/>
<circle cx="101" cy="286.6" r="2.84"/>
<circle cx="107.9" cy="286.6" r="2.84"/>
<circle cx="114.9" cy="286.6" r="2.84"/>
<circle cx="121.9" cy="286.6" r="2.84"/>
<circle cx="128.9" cy="286.6" r="2.84"/>
<circle cx="135.9" cy="286.6" r="2.84"/>
<circle cx="142.9" cy="286.6" r="2.84"/>
<circle cx="149.9" cy="286.6" r="2.84"/>
<circle cx="73" cy="304.3" r="2.84"/>
<circle cx="80" cy="304.3" r="2.84"/>
<circle cx="87" cy="304.3" r="2.84"/>
<circle cx="94" cy="304.3" r="2.84"/>
<circle cx="101" cy="304.3" r="2.84"/>
<circle cx="107.9" cy="304.3" r="2.84"/>
<circle cx="114.9" cy="304.3" r="2.84"/>
<circle cx="121.9" cy="304.3" r="2.84"/>
<circle cx="128.9" cy="304.3" r="2.84"/>
<circle cx="135.9" cy="304.3" r="2.84"/>
<circle cx="142.9" cy="304.3" r="2.84"/>
<circle cx="149.9" cy="304.3" r="2.84"/>
<circle cx="72.1" cy="330.4" r="2.82"/>
<circle cx="73" cy="321.5" r="2.84"/>
<circle cx="80" cy="321.5" r="2.84"/>
<circle cx="87" cy="321.5" r="2.84"/>
<circle cx="94" cy="321.5" r="2.84"/>
<circle cx="101" cy="321.5" r="2.84"/>
<circle cx="103.5" cy="321.5" r="2.84"/>
<circle cx="107.9" cy="321.5" r="2.84"/>
<circle cx="110.5" cy="321.5" r="2.84"/>
<circle cx="114.9" cy="321.5" r="2.84"/>
<circle cx="117.5" cy="321.5" r="2.84"/>
<circle cx="121.9" cy="321.5" r="2.84"/>
<circle cx="128.9" cy="321.5" r="2.84"/>
<circle cx="135.9" cy="321.5" r="2.84"/>
<circle cx="142.9" cy="321.5" r="2.84"/>
<circle cx="149.9" cy="321.5" r="2.84"/>
</g>
<g fill="none" stroke="#840000" stroke-width=".3">
<path d="M469.6 99.7h3.1M474.7 99.7h3.1M388.4 165.1h3M399.2 165.1h3M514.5 177.3h2.3v5.1h-2.3zM421.4 191.8h3M505.2 184.4h3.1M523 184.4h3M421.4 215.9h3M411.2 259.8h3.1M491.2 258.7h3.1M500.1 258.7h3.1"/>
<path d="M509 258.7h3.1M517.9 258.7h3.1M526.8 258.7h3M429 260.4h3.1M209.9 317.5h3.1M462.7 311.2h3M416.3 327.1h3.1M497 389.9l-.4-.1-.3 .3 .1 .6h.6M498.2 389.9l-.4-.1-.2 .2 .1 .3 .5 .1v.3h-.6M570.9 402.4l-.4 1h.9M571.2 402.9v1"/>
</g>
<path d="M497.2 399.3l.9-.1 .2-.3-.1-.4-.2-.2h-.7l-.2 2 1-.1 .2-.5-.4-.4" fill="none" stroke="#840000" stroke-width=".41"/>
<g fill="none" stroke="#840000" stroke-width=".33">
<path d="M469.6 98.7h3.1M474.7 98.7h3.1M388.4 164.1h3M399.2 164.1h3M421.4 190.8h3M505.2 185.5h3.1M523 185.5h3M421.4 214.9h3M411.2 258.7h3.1M429 259.4h3.1M491.2 259.8h3.1M500.1 259.8h3.1"/>
<path d="M509 259.8h3.1M517.9 259.8h3.1M526.8 259.8h3M209.9 316.5h3.1M462.7 310.2h3M416.3 326.1h3.1"/>
</g>
<g fill="none" stroke="#008400" stroke-width=".26">
<path d="M50.2 76.4v102.8M75.6 76.4v102.8h3.8M101 76.4v102.8h3.8M126.4 76.4v102.8h3.8M151.8 76.4v121.9h3.8M177.2 76.4v121.9h3.8M202.6 76.4v121.9h3.8M228 76.4v102.8h3.8M253.4 76.4v102.8h3.8M278.8 76.4v102.8h3.8M304.2 76.4v102.8h3.8M329.6 76.4v104.1"/>
<path d="M487 78.9h-1.2v15.2M542.9 78.9h1.9M41.3 83.4h301v.6M62.9 83.4v.6M62.9 91.6v.6M88.3 83.4v.6M88.3 91.6v.6M113.7 83.4v.6M113.7 91.6v.6M139.1 83.4v.6M139.1 91.6v.6M164.5 83.4v.6"/>
<path d="M164.5 91.6v.6M189.9 83.4v.6M189.9 91.6v.6M215.3 83.4v.6M215.3 91.6v.6M240.7 83.4v.6M240.7 91.6v.6M266.1 83.4v.6M266.1 91.6v.6M291.5 83.4v.6M291.5 91.6v.6M316.9 83.4v.6"/>
<path d="M316.9 91.6v.6M342.3 91.6v.6M390.5 95.4h3.2M476.2 94.1v2.6M482.6 86.5h4.4M485.8 82.7h1.2M485.8 90.3h1.2M487 94.1h-15.8v2.6M542.9 86.5h1.9M542.9 89.1h1.9M542.9 91.6h1.9M542.9 84h1.9"/>
<path d="M542.9 81.4h1.9M542.9 95.4h1.9M542.9 98h1.9M41.3 109.4h301v.6M50.2 101.1h3.8M62.9 109.4v.6M62.9 117.6v.7M75.6 101.1h3.8M88.3 109.4v.6M88.3 117.6v.7M101 101.1h3.8M113.7 109.4v.6"/>
<path d="M113.7 117.6v.7M126.4 101.1h3.8M139.1 109.4v.6M139.1 117.6v.7M151.8 101.1h3.8M164.5 109.4v.6M164.5 117.6v.7M177.2 101.1h3.8M189.9 109.4v.6M189.9 117.6v.7M202.6 101.1h3.8M215.3 109.4v.6"/>
<path d="M215.3 117.6v.7M228 101.1h3.8M240.7 109.4v.6M240.7 117.6v.7M253.4 101.1h3.8M266.1 109.4v.6M266.1 117.6v.7M278.8 101.1h3.8M291.5 109.4v.6M291.5 117.6v.7M304.2 101.1h3.8M316.9 109.4v.6"/>
<path d="M316.9 117.6v.7M329.6 101.1h3.8M342.3 117.6v.7M471.2 101.8v1.2h5M476.2 101.8v2.5M485.8 105.6h1.2M485.8 103h1.2M485.8 113.2h1.2M485.8 115.7h1.2M542.9 109.4h1.9M542.9 101.8h1.9M542.9 113.2h1.9"/>
<path d="M542.9 115.7h1.9M542.9 106.8h1.9M542.9 104.3h1.9M542.9 118.3h1.9M41.3 135.4h301v.7M50.2 127.2h3.8M62.9 135.4v.7M75.6 127.2h3.8M88.3 135.4v.7M101 127.2h3.8M113.7 135.4v.7M126.4 127.2h3.8"/>
<path d="M139.1 135.4v.7M151.8 127.2h3.8M164.5 135.4v.7M177.2 127.2h3.8M189.9 135.4v.7M202.6 127.2h3.8M215.3 135.4v.7M228 127.2h3.8M240.7 135.4v.7M253.4 127.2h3.8M266.1 135.4v.7M278.8 127.2h3.8"/>
<path d="M291.5 135.4v.7M304.2 127.2h3.8M316.9 135.4v.7M329.6 127.2h3.8M485.8 129.7h1.2M485.8 132.2h1.2M485.8 138.6h1.2M485.8 122.1h1.2M485.8 124.6h1.2M542.9 125.9h1.9M542.9 139.9h1.9M542.9 137.3h1.9"/>
<path d="M542.9 120.8h1.9M542.9 134.8h2.6M542.9 128.4h1.9M542.9 123.4h1.9M50.2 153.2h3.8M62.9 143.7v.6M75.6 153.2h3.8M88.3 143.7v.6M101 153.2h3.8M113.7 143.7v.6M126.4 153.2h3.8M139.1 143.7v.6"/>
<path d="M151.8 153.2h3.8M164.5 143.7v.6M177.2 153.2h3.8M189.9 143.7v.6M202.6 153.2h3.8M215.3 143.7v.6M228 153.2h3.8M240.7 143.7v.6M253.4 153.2h3.8M266.1 143.7v.6M278.8 153.2h3.8M291.5 143.7v.6"/>
<path d="M304.2 153.2h3.8M316.9 143.7v.6M329.6 153.2h3.8M342.3 143.7v.6M388.6 154.5h1.3M389.9 148.8v-1.3h10.8v1.3M389.9 153.8v1.3M395.6 146.2v1.3M400.7 153.8v1.3M400.7 154.5h1.3M414.7 150.7h1.9M414.7 145.6h1.9"/>
<path d="M431.8 150.7h1.3M431.8 145.6h1.3M485.1 156.4h1.9M485.1 153.8h1.9M485.1 151.3h1.9M485.8 142.4h1.2M487 148.8h-1.9v11.4M542.9 156.4h1.9M542.9 142.4h1.9M542.9 150h1.9M542.9 152.6h1.9M542.9 147.5h1.9"/>
<path d="M542.9 144.9h1.9M41.3 161.5h301v.6M48.3 179.2h5.7M62.9 161.5v.6M62.9 169.7v.6h-2.6M88.3 161.5v.6M88.3 169.7v.6M113.7 161.5v.6M113.7 169.7v.6M139.1 161.5v.6M139.1 169.7v.6M151.8 179.2h3.8"/>
<path d="M164.5 161.5v.6M164.5 170.3v-.6h7.6v17.8h-7.6v1.9M177.2 179.2h3.8M189.9 161.5v.6M189.9 170.3v-.6h7.6v17.8h-7.6v1.9M202.6 179.2h3.8M215.3 161.5v.6M215.3 170.3v-.6h7.6v17.8h-7.6v1.9M240.7 161.5v.6M240.7 169.7v.6M266.1 161.5v.6M266.1 169.7v.6"/>
<path d="M291.5 161.5v.6M291.5 169.7v.6M316.9 161.5v.6M316.9 169.7v.6M329.6 179.2h3.8M344.8 169.7h-2.5v.6M389.9 160.2v1.9M389.9 167.2v.6M400.7 160.2v1.9M400.7 167.2v.6M414.7 161.5h1.9M414.7 166.5h1.9"/>
<path d="M431.8 161.5h1.3M431.8 166.5h1.3M506.7 178.6v3.8M506.7 179.9h5.1M515.6 172.3v2.5M519.4 179.9h5.1M524.5 178.6v3.8M400 195.1h1.3M411.5 195.1h19M422.9 187.5v1.3M422.9 193.8v1.3M506.7 187.5v1.3h17.8v-1.3"/>
<path d="M515.6 185v3.8M404.5 210.4h3.8M406.4 204v6.4M415.9 210.4h14.6M419.1 210.4v2.5M419.1 218v1.2M422.9 210.4v2.5M422.9 218v1.2M338.5 238.9h1.9M417.8 238.3h-5.1v18.4M425.4 238.3h5.1v19M68.6 256.7v54.6h81.3"/>
<path d="M68.6 259.2h81.3M234.3 251h5.7M234.3 245.9h11.4M234.3 258.6h4.5M236.2 251v2.5h-1.9M236.2 258.6v2.6h-1.9M288.3 242.1h1.9M288.3 249.7h1.9M288.3 244.6h1.9M288.3 247.2h1.9M338.5 249.1h1.9M338.5 246.5h1.9"/>
<path d="M338.5 251.6h1.9M338.5 244h1.9M338.5 241.5h1.9M396.9 250.4h1.2M403.2 250.4h10.8M407 248.5v3.1M407 256.7v1.3M421.6 258v9.5M429.3 250.4h8.8M492.8 256.7v-1.9h35.5v1.9M501.6 254.8v1.9M510.5 252.9v3.8"/>
<path d="M519.4 254.8v1.9M68.6 276.4h81.3M73 271.9h83.8v53.4h-83.8M234.3 263.7h4.5M234.3 266.2h6.4M236.2 263.7v2.5M245.7 266.2h1.9M288.3 270.7h1.9M288.3 278.3h1.9M288.3 273.2h1.9M288.3 275.8h1.9M338.5 270.7h1.9"/>
<path d="M338.5 278.3h1.9M338.5 273.2h1.9M338.5 275.8h1.9M412.7 261.8v3.8h17.8v-3.2M492.8 261.8v1.9h35.5v-1.9M501.6 261.8v1.9M510.5 261.8v3.2M519.4 261.8v1.9M68.6 294.2h81.3M73 281.5v1.2M73 299.3v1.2M73 290.4h83.8"/>
<path d="M80 281.5v1.2M80 299.3v1.2M87 281.5v1.2M87 299.3v1.2M94 281.5v1.2M94 299.3v1.2M101 281.5v1.2M101 299.3v1.2M107.9 281.5v1.2M107.9 299.3v1.2M114.9 281.5v1.2M114.9 299.3v1.2"/>
<path d="M121.9 281.5v1.2M121.9 299.3v1.2M128.9 281.5v1.2M128.9 299.3v1.2M135.9 281.5v1.2M135.9 299.3v1.2M142.9 281.5v1.2M142.9 299.3v1.2M149.9 281.5v1.2M149.9 299.3v1.2M293.4 299.9v3.2M73 316.4v1.3"/>
<path d="M73 308.1h83.8M80 316.4v1.3M87 316.4v1.3M94 316.4v1.3M101 316.4v1.3M101 317h2.5v.7M107.9 317h2.6v.7M107.9 316.4v1.3M114.9 317h2.6v.7M114.9 316.4v1.3M121.9 316.4v1.3M128.9 316.4v1.3"/>
<path d="M135.9 316.4v1.3M142.9 316.4v1.3M149.9 316.4v1.3M206.4 313.2h5.1M211.5 312v2.5M211.5 319.6v1.2h-5.1v1.3M284.5 310.7h1.2M293.4 301.8h49.5v1.3M293.4 318.3v1.3h49.5v-1.3M301 310.7h1.3M309.9 301.8v1.3M309.9 318.3v2.5"/>
<path d="M317.5 310.7h1.3M326.4 301.8v1.3M326.4 318.3v1.3M334 310.7h1.3M398.8 306.9h2.5v1.9M407.7 306.9h-1.3v1.9M412.7 306.9h1.3M459.1 306.9h7.6M464.2 306.9v1.2M464.2 313.2v1.3h-5.1v1.3M474.3 306.9h.7M56.5 330.4h1.9"/>
<path d="M63.5 330.4h1.9M64.8 330.4v1.9M64.8 337.4v2.5h8.2M73 335.4v7M284.5 334.2h1.2M293.4 325.3h49.5v1.3M293.4 324v2.6M301 334.2h1.3M309.9 325.3v1.3M317.5 334.2h1.3M326.4 325.3v1.3M334 334.2h1.3"/>
<path d="M388.6 321.5h2.6M401.3 334.2v1.2h-2.5M406.4 334.2v1.2h1.3M412.7 335.4h1.3M416.6 321.5h1.2v2.5M417.8 329.1v2.5M293.4 341.8v1.3h49.5v-1.3M309.9 341.8v2.5M326.4 341.8v1.3"/>
</g>
<g fill="#008400" stroke="#008400" stroke-width=".26">
<circle cx="506.7" cy="179.9" r=".51"/>
<circle cx="524.5" cy="179.9" r=".51"/>
<circle cx="515.6" cy="188.8" r=".51"/>
<circle cx="88.3" cy="83.4" r=".51"/>
<circle cx="113.7" cy="83.4" r=".51"/>
<circle cx="164.5" cy="83.4" r=".51"/>
<circle cx="189.9" cy="83.4" r=".51"/>
<circle cx="215.3" cy="83.4" r=".51"/>
<circle cx="266.1" cy="83.4" r=".51"/>
<circle cx="291.5" cy="83.4" r=".51"/>
<circle cx="139.1" cy="83.4" r=".51"/>
<circle cx="240.7" cy="83.4" r=".51"/>
<circle cx="316.9" cy="83.4" r=".51"/>
<circle cx="62.9" cy="109.4" r=".51"/>
<circle cx="88.3" cy="109.4" r=".51"/>
<circle cx="113.7" cy="109.4" r=".51"/>
<circle cx="164.5" cy="109.4" r=".51"/>
<circle cx="189.9" cy="109.4" r=".51"/>
<circle cx="215.3" cy="109.4" r=".51"/>
<circle cx="266.1" cy="109.4" r=".51"/>
<circle cx="291.5" cy="109.4" r=".51"/>
<circle cx="139.1" cy="109.4" r=".51"/>
<circle cx="240.7" cy="109.4" r=".51"/>
<circle cx="316.9" cy="109.4" r=".51"/>
<circle cx="62.9" cy="135.4" r=".51"/>
<circle cx="88.3" cy="135.4" r=".51"/>
<circle cx="113.7" cy="135.4" r=".51"/>
<circle cx="164.5" cy="135.4" r=".51"/>
<circle cx="189.9" cy="135.4" r=".51"/>
<circle cx="215.3" cy="135.4" r=".51"/>
<circle cx="266.1" cy="135.4" r=".51"/>
<circle cx="291.5" cy="135.4" r=".51"/>
<circle cx="139.1" cy="135.4" r=".51"/>
<circle cx="240.7" cy="135.4" r=".51"/>
<circle cx="316.9" cy="135.4" r=".51"/>
<circle cx="50.2" cy="101.1" r=".51"/>
<circle cx="75.6" cy="127.2" r=".51"/>
<circle cx="101" cy="101.1" r=".51"/>
<circle cx="101" cy="127.2" r=".51"/>
<circle cx="126.4" cy="101.1" r=".51"/>
<circle cx="126.4" cy="127.2" r=".51"/>
<circle cx="151.8" cy="101.1" r=".51"/>
<circle cx="151.8" cy="127.2" r=".51"/>
<circle cx="177.2" cy="101.1" r=".51"/>
<circle cx="177.2" cy="127.2" r=".51"/>
<circle cx="202.6" cy="101.1" r=".51"/>
<circle cx="202.6" cy="127.2" r=".51"/>
<circle cx="228" cy="101.1" r=".51"/>
<circle cx="228" cy="127.2" r=".51"/>
<circle cx="253.4" cy="101.1" r=".51"/>
<circle cx="253.4" cy="127.2" r=".51"/>
<circle cx="278.8" cy="101.1" r=".51"/>
<circle cx="278.8" cy="127.2" r=".51"/>
<circle cx="304.2" cy="101.1" r=".51"/>
<circle cx="304.2" cy="127.2" r=".51"/>
<circle cx="329.6" cy="101.1" r=".51"/>
<circle cx="329.6" cy="127.2" r=".51"/>
<circle cx="62.9" cy="161.5" r=".51"/>
<circle cx="88.3" cy="161.5" r=".51"/>
<circle cx="113.7" cy="161.5" r=".51"/>
<circle cx="164.5" cy="161.5" r=".51"/>
<circle cx="189.9" cy="161.5" r=".51"/>
<circle cx="215.3" cy="161.5" r=".51"/>
<circle cx="266.1" cy="161.5" r=".51"/>
<circle cx="291.5" cy="161.5" r=".51"/>
<circle cx="139.1" cy="161.5" r=".51"/>
<circle cx="240.7" cy="161.5" r=".51"/>
<circle cx="316.9" cy="161.5" r=".51"/>
<circle cx="50.2" cy="127.2" r=".51"/>
<circle cx="75.6" cy="101.1" r=".51"/>
<circle cx="164.5" cy="169.7" r=".51"/>
<circle cx="151.8" cy="153.2" r=".51"/>
<circle cx="177.2" cy="153.2" r=".51"/>
<circle cx="189.9" cy="169.7" r=".51"/>
<circle cx="177.2" cy="179.2" r=".51"/>
<circle cx="151.8" cy="179.2" r=".51"/>
<circle cx="202.6" cy="179.2" r=".51"/>
<circle cx="215.3" cy="169.7" r=".51"/>
<circle cx="211.5" cy="313.2" r=".51"/>
<circle cx="206.4" cy="320.8" r=".51"/>
<circle cx="407" cy="250.4" r=".51"/>
<circle cx="464.2" cy="306.9" r=".51"/>
<circle cx="459.1" cy="314.5" r=".51"/>
<circle cx="75.6" cy="153.2" r=".51"/>
<circle cx="101" cy="153.2" r=".51"/>
<circle cx="126.4" cy="153.2" r=".51"/>
<circle cx="202.6" cy="153.2" r=".51"/>
<circle cx="228" cy="153.2" r=".51"/>
<circle cx="253.4" cy="153.2" r=".51"/>
<circle cx="278.8" cy="153.2" r=".51"/>
<circle cx="304.2" cy="153.2" r=".51"/>
<circle cx="329.6" cy="153.2" r=".51"/>
<circle cx="64.8" cy="330.4" r=".51"/>
<circle cx="101" cy="317" r=".51"/>
<circle cx="108" cy="317" r=".51"/>
<circle cx="114.9" cy="317" r=".51"/>
<circle cx="73" cy="311.3" r=".51"/>
<circle cx="80" cy="311.3" r=".51"/>
<circle cx="87" cy="311.3" r=".51"/>
<circle cx="94" cy="311.3" r=".51"/>
<circle cx="101" cy="311.3" r=".51"/>
<circle cx="108" cy="311.3" r=".51"/>
<circle cx="114.9" cy="311.3" r=".51"/>
<circle cx="121.9" cy="311.3" r=".51"/>
<circle cx="128.9" cy="311.3" r=".51"/>
<circle cx="135.9" cy="311.3" r=".51"/>
<circle cx="142.9" cy="311.3" r=".51"/>
<circle cx="73" cy="259.2" r=".51"/>
<circle cx="80" cy="259.2" r=".51"/>
<circle cx="87" cy="259.2" r=".51"/>
<circle cx="94" cy="259.2" r=".51"/>
<circle cx="101" cy="259.2" r=".51"/>
<circle cx="114.9" cy="259.2" r=".51"/>
<circle cx="121.9" cy="259.2" r=".51"/>
<circle cx="128.9" cy="259.2" r=".51"/>
<circle cx="135.9" cy="259.2" r=".51"/>
<circle cx="142.9" cy="259.2" r=".51"/>
<circle cx="68.6" cy="276.4" r=".51"/>
<circle cx="73" cy="276.4" r=".51"/>
<circle cx="80" cy="276.4" r=".51"/>
<circle cx="87" cy="276.4" r=".51"/>
<circle cx="94" cy="276.4" r=".51"/>
<circle cx="101" cy="276.4" r=".51"/>
<circle cx="108" cy="276.4" r=".51"/>
<circle cx="114.9" cy="276.4" r=".51"/>
<circle cx="121.9" cy="276.4" r=".51"/>
<circle cx="128.9" cy="276.4" r=".51"/>
<circle cx="135.9" cy="276.4" r=".51"/>
<circle cx="142.9" cy="276.4" r=".51"/>
<circle cx="68.6" cy="294.2" r=".51"/>
<circle cx="73" cy="294.2" r=".51"/>
<circle cx="80" cy="294.2" r=".51"/>
<circle cx="87" cy="294.2" r=".51"/>
<circle cx="94" cy="294.2" r=".51"/>
<circle cx="101" cy="294.2" r=".51"/>
<circle cx="108" cy="294.2" r=".51"/>
<circle cx="114.9" cy="294.2" r=".51"/>
<circle cx="121.9" cy="294.2" r=".51"/>
<circle cx="128.9" cy="294.2" r=".51"/>
<circle cx="135.9" cy="294.2" r=".51"/>
<circle cx="142.9" cy="294.2" r=".51"/>
<circle cx="68.6" cy="259.2" r=".51"/>
<circle cx="73" cy="339.9" r=".51"/>
<circle cx="156.8" cy="308.1" r=".51"/>
<circle cx="156.8" cy="290.4" r=".51"/>
<circle cx="412.7" cy="250.4" r=".51"/>
<circle cx="236.2" cy="251" r=".51"/>
<circle cx="421.6" cy="265.6" r=".51"/>
<circle cx="485.1" cy="153.8" r=".51"/>
<circle cx="485.1" cy="151.3" r=".51"/>
<circle cx="485.1" cy="156.4" r=".51"/>
<circle cx="485.8" cy="82.7" r=".51"/>
<circle cx="485.8" cy="86.5" r=".51"/>
<circle cx="485.8" cy="90.3" r=".51"/>
<circle cx="422.9" cy="210.4" r=".51"/>
<circle cx="419.1" cy="210.4" r=".51"/>
<circle cx="422.9" cy="195.1" r=".51"/>
<circle cx="501.6" cy="254.8" r=".51"/>
<circle cx="501.6" cy="263.7" r=".51"/>
<circle cx="510.5" cy="254.8" r=".51"/>
<circle cx="510.5" cy="263.7" r=".51"/>
<circle cx="519.4" cy="254.8" r=".51"/>
<circle cx="519.4" cy="263.7" r=".51"/>
<circle cx="430.5" cy="250.4" r=".51"/>
<circle cx="326.4" cy="325.3" r=".51"/>
<circle cx="309.9" cy="325.3" r=".51"/>
<circle cx="293.4" cy="325.3" r=".51"/>
<circle cx="309.9" cy="301.8" r=".51"/>
<circle cx="293.4" cy="301.8" r=".51"/>
<circle cx="326.4" cy="301.8" r=".51"/>
<circle cx="309.9" cy="319.6" r=".51"/>
<circle cx="326.4" cy="319.6" r=".51"/>
<circle cx="326.4" cy="343.1" r=".51"/>
<circle cx="309.9" cy="343.1" r=".51"/>
<circle cx="395.6" cy="147.5" r=".51"/>
<circle cx="389.9" cy="154.5" r=".51"/>
<circle cx="400.7" cy="154.5" r=".51"/>
<circle cx="62.9" cy="83.4" r=".51"/>
<circle cx="50.2" cy="179.2" r=".51"/>
<circle cx="50.2" cy="153.2" r=".51"/>
<circle cx="329.6" cy="179.2" r=".51"/>
<circle cx="342.3" cy="169.7" r=".51"/>
<circle cx="73" cy="325.3" r=".51"/>
<circle cx="80" cy="271.9" r=".51"/>
<circle cx="80" cy="290.4" r=".51"/>
<circle cx="80" cy="308.1" r=".51"/>
<circle cx="80" cy="325.3" r=".51"/>
<circle cx="87" cy="271.9" r=".51"/>
<circle cx="87" cy="290.4" r=".51"/>
<circle cx="87" cy="308.1" r=".51"/>
<circle cx="87" cy="325.3" r=".51"/>
<circle cx="94" cy="271.9" r=".51"/>
<circle cx="94" cy="290.4" r=".51"/>
<circle cx="94" cy="308.1" r=".51"/>
<circle cx="94" cy="325.3" r=".51"/>
<circle cx="101" cy="290.4" r=".51"/>
<circle cx="101" cy="308.1" r=".51"/>
<circle cx="101" cy="325.3" r=".51"/>
<circle cx="103.5" cy="325.3" r=".51"/>
<circle cx="108" cy="271.9" r=".51"/>
<circle cx="108" cy="290.4" r=".51"/>
<circle cx="108" cy="308.1" r=".51"/>
<circle cx="108" cy="325.3" r=".51"/>
<circle cx="110.5" cy="325.3" r=".51"/>
<circle cx="114.9" cy="290.4" r=".51"/>
<circle cx="114.9" cy="308.1" r=".51"/>
<circle cx="114.9" cy="325.3" r=".51"/>
<circle cx="117.5" cy="325.3" r=".51"/>
<circle cx="121.9" cy="271.9" r=".51"/>
<circle cx="121.9" cy="290.4" r=".51"/>
<circle cx="121.9" cy="308.1" r=".51"/>
<circle cx="121.9" cy="325.3" r=".51"/>
<circle cx="128.9" cy="271.9" r=".51"/>
<circle cx="128.9" cy="290.4" r=".51"/>
<circle cx="128.9" cy="308.1" r=".51"/>
<circle cx="128.9" cy="325.3" r=".51"/>
<circle cx="135.9" cy="271.9" r=".51"/>
<circle cx="135.9" cy="290.4" r=".51"/>
<circle cx="135.9" cy="308.1" r=".51"/>
<circle cx="135.9" cy="325.3" r=".51"/>
<circle cx="142.9" cy="271.9" r=".51"/>
<circle cx="142.9" cy="290.4" r=".51"/>
<circle cx="142.9" cy="308.1" r=".51"/>
<circle cx="142.9" cy="325.3" r=".51"/>
<circle cx="149.9" cy="271.9" r=".51"/>
<circle cx="149.9" cy="290.4" r=".51"/>
<circle cx="149.9" cy="308.1" r=".51"/>
<circle cx="149.9" cy="325.3" r=".51"/>
<circle cx="62.9" cy="170.3" r=".51"/>
<circle cx="101" cy="271.9" r=".51"/>
<circle cx="108" cy="259.2" r=".51"/>
<circle cx="114.9" cy="271.9" r=".51"/>
<circle cx="236.2" cy="266.2" r=".51"/>
<circle cx="406.4" cy="210.4" r=".51"/>
<circle cx="485.8" cy="94.1" r=".51"/>
<circle cx="476.2" cy="94.1" r=".51"/>
<circle cx="476.2" cy="103" r=".51"/>
<circle cx="236.2" cy="263.7" r=".51"/>
<circle cx="236.2" cy="258.6" r=".51"/>
</g>
<g fill="none" stroke="#840000" stroke-width="1.3">
<circle cx="386.7" cy="85.3" r="1.27"/>
<circle cx="386.7" cy="80.2" r="1.27"/>
<circle cx="386.7" cy="90.3" r="1.27"/>
<circle cx="386.7" cy="95.4" r="1.27"/>
<circle cx="432.4" cy="87.2" r="1.27"/>
<circle cx="432.4" cy="98.6" r="1.27"/>
<circle cx="432.4" cy="81.4" r="1.27"/>
<circle cx="432.4" cy="92.9" r="1.27"/>
<circle cx="386.7" cy="100.5" r="1.27"/>
<circle cx="386.7" cy="105.6" r="1.27"/>
<circle cx="432.4" cy="104.3" r="1.27"/>
<circle cx="432.4" cy="110" r="1.27"/>
</g>
<g fill="none" stroke="#008484" stroke-width=".26">
<path d="M401 97.3l.6-.1-.1-.2-.5 .1 .1 .6h.4M401 86.6l.6-.1-.1-.3-.5 .1 .1 .6h.4M401.2 91.7l.7-.1-.1-.3-.6 .2 .1 .6h.5M401.2 81.5l.7-.1-.1-.2-.6 .1 .1 .6h.5M443.5 88.5l.3 .4M443.8 88.1l-.5 .5M447.2 99.5v1.1l-.2 .2-.3-.1M447.2 99.6l-.3-.1-.3 .3 .1 .5h.5M509.1 94.2h1M509.6 93.7v1M523.1 94.7v1.3M523.2 97.2v1.3"/>
<path d="M523.6 94.8l.5-.1 .3 .4-.8 .9h.8M523.7 97.4l.5-.2 .2 .4-.8 .9h.8M401.2 101.8l.7-.1-.1-.2-.6 .1 .1 .6h.5M401.2 106.9l.7-.1-.1-.2-.6 .1 .1 .6h.5M505.7 103.6v-1.3l.4 .9 .4-.9v1.3M505.7 105.5h.6v-.5l-.6-.1v1.2M509 113.8v-1.3l.4 .9 .5-.9v1.3M511.1 112.6h-.6v.4l.5 .2 .1 .3-.2 .3-.5-.1M517 101.1v1.2M517.6 101.2l.4-.1 .3 .3-.8 .9h.8M519.2 115.1h-.6l-.1 .4a.5 .5 0 0 1 .5 .2 .5 .5 0 0 1 0 .5h-.6M519.5 101.2a.56 .56 0 0 0-.8 .5 .56 .56 0 0 0 .8 .5"/>
<path d="M519.7 115a.64 .64 0 0 1 .8 .7 .64 .64 0 0 1-.8 .6zM520.8 116.3l.4-1.3 .5 1.3M520.9 115.9h.6M522.1 103.6v1.3M522.6 103.7l.5-.1 .2 .4-.7 .9h.7M523.1 112.5v1.3M523.2 115v1.3M523.3 106.1v1.3M523.6 112.6l.5-.1 .3 .3-.8 1h.8M523.7 115.2l.5-.2 .2 .4-.8 .9h.8M523.9 106.3l.5-.2 .2 .4-.8 .9h.8M508.4 121.4v1.2l-.8-1.2v1.2"/>
<path d="M509.5 123.9h.7M509.9 123.9v1.3M513 129a.64 .64 0 0 1 .7 .6 .64 .64 0 0 1-.7 .7zM514 130.3l.5-1.3 .4 1.3M514.1 129.9h.7M515.4 131.7a.56 .56 0 0 0-.8 .5 .56 .56 0 0 0 .8 .5M515.9 131.5v1.3h.6M516.7 122.6l-.1 1.1-.4 .2M520.9 139.2a.64 .64 0 0 1 .7 .6 .64 .64 0 0 1-.7 .6zM525.6 120.1l-.1 1.1-.4 .2M433.6 156.8h-.4l-.2 .2 .1 .6h.5M433.6 141l-.4-.1-.2 .2 .1 .6h.5"/>
<path d="M434.1 156.9l.5-.1 .1 .8M434.1 141h.5l.1 .7M434.1 140.5v1.2M434.1 156.4v1.2M508.8 148h-.6v1.3M509.2 148.8h1M520.9 141.7a.64 .64 0 0 1 .7 .6 .64 .64 0 0 1-.7 .7zM522 143l.4-1.3 .4 1.3M522 140.4l.4-1.2 .4 1.2M522.1 142.6h.6M522.1 140.1h.6M344.8 234.1l.6-.1-.1-.3-.4-.1-.1 .2v.6h.5"/>
<path d="M225.6 257.9a.64 .64 0 0 1 .7 .6 .64 .64 0 0 1-.7 .7zM226.8 258.7h1M229.6 241.6l.6-.1-.1-.2-.3-.1-.2 .2v.6h.5M293.5 240.1l.6-.1-.1-.3h-.4l-.1 .2v.6h.5M397.7 256.1l.4-.1v-.3h-.4v.8M405.5 256.1l.4-.1v-.3h-.4v.8M405.7 256.1l.3 .4M414.6 247.3v-.8l.3 .6 .2-.6v.8M428.2 246.5h.5l-.3 .3 .3 .2v.2h-.5M428.4 257.4v.6M223.1 271.3l.6-.1 .1-.5-.7-.1v1.3M223.1 273.8h.6l.1-.5-.7-.2v1.3"/>
<path d="M223.3 278.2h.7M223.4 271.3l.5 .6M223.6 278.2v1.3M225.6 260.4a.64 .64 0 0 1 .7 .7 .64 .64 0 0 1-.7 .6zM226.8 261.2h1M293.5 268.7l.6-.1-.1-.3h-.4l-.1 .1v.7h.5M343.6 268.7l.6-.1v-.3h-.4l-.2 .1 .1 .7h.5M223.1 286.5h.6l.1-.5-.7-.2v1.3M223.1 289h.6l.1-.5-.7-.1v1.3M223.3 280.8h.7M223.3 296h.7M223.3 293.5h.7"/>
<path d="M223.4 286.5l.5 .6M223.6 293.5v1.2M411.3 305.4h.5M415.7 315.8v1l.2 .2 .5-.2v-1M428.8 315.8h-.4l-.2 .5v.6l.6 .1v-.7l-.4-.1-.2 .3"/>
</g>
<path d="M404 250.9h.3M404.7 250.9l-.3 .2 .1 .2h.2M208.9 331.5h-.4l-.2 .2 .1 .6h.5M208.9 331.1v1.2" fill="none" stroke="#0000c2" stroke-width=".26"/>
<g fill="#840000" stroke="#840000" stroke-width=".26">
<path d="M211.5 275.1l1.2 .1-.3 .5-.4 .1-.4-.2z"/>
<path d="M211.6 267l.7-.1 .4 .6h-1.2z"/>
<path d="M211.5 267.5h1.2v7.6h-1.2z"/>
<path d="M220.2 265h1.3v1.2h-1.3z"/>
<path d="M218.3 261.2l1.3 2.5h-2.6z"/>
<path d="M283.2 249.6h.9v.3h-.9z"/>
<path d="M283.2 247.1h.9v.2h-.9z"/>
<path d="M283.2 244.5h.9v.3h-.9z"/>
<path d="M283.2 242h.9v.2h-.9z"/>
<path d="M283.2 278.2h.9v.2h-.9z"/>
<path d="M283.2 275.6h.9v.3h-.9z"/>
<path d="M283.2 273.1h.9v.2h-.9z"/>
<path d="M283.2 270.6h.9v.2h-.9z"/>
<path d="M333.4 278.2h.8v.2h-.8z"/>
<path d="M333.4 275.6h.8v.3h-.8z"/>
<path d="M333.4 273.1h.8v.2h-.8z"/>
<path d="M333.4 270.6h.8v.2h-.8z"/>
<path d="M333.4 251.5h.8v.3h-.8z"/>
<path d="M333.4 249h.8v.2h-.8z"/>
<path d="M333.4 246.4h.8v.3h-.8z"/>
<path d="M333.4 243.9h.8v.2h-.8z"/>
<path d="M333.4 241.3h.8v.3h-.8z"/>
<path d="M333.4 238.8h.8v.3h-.8z"/>
<path d="M404.7 195.7l1.1 .6-.5 .5z"/>
<circle cx="73" cy="332.1" r=".28"/>
<circle cx="215.8" cy="266.9" r=".63"/>
<circle cx="420.4" cy="164" r=".25"/>
<circle cx="420.4" cy="148.1" r=".25"/>
<circle cx="403.9" cy="316.4" r=".25"/>
<circle cx="403.9" cy="318.9" r=".25"/>
<circle cx="397.5" cy="321.5" r=".25"/>
<circle cx="410.2" cy="321.5" r=".25"/>
<circle cx="403.9" cy="324" r=".25"/>
<circle cx="403.9" cy="326.6" r=".25"/>
</g>
<g fill="none" stroke="#0000c2" stroke-width=".51">
<path d="M408.2 116.8a.65 .65 0 0 0-1 .2v.4a.77 .77 0 0 1 1 .4l-.5 .5-.7-.1M449.5 116.6l-.5 2.3a.73 .73 0 0 1-.9 .1M449.5 116.8a.85 .85 0 0 0-1.3 .3l-.1 .7 .2 .4h1M451.5 116.8a.65 .65 0 0 0-1 .2l.1 .4a.77 .77 0 0 1 .9 .4l-.4 .5-.8-.1M408.5 138.3a.62 .62 0 0 0-1 .4l.1 .3a.73 .73 0 0 1 .9 .5l-.4 .4-.7-.1M414 183.3l-.1 1.6a.68 .68 0 0 0 1-.1M415 183.3l-.2 1.7M416.3 183.3l-.2 1.7M416.4 182.5l-.1 .2M417.1 183.3h1M417.6 182.5l-.3 2.1 .1 .3 .5 .1M357.6 255.3a.61 .61 0 0 1 1.1 .1l-.2 1.4"/>
<path d="M361 255.1l-.4 2.3a.73 .73 0 0 1-1 .1M361 255.2a.85 .85 0 0 0-1.3 .3v.8l.1 .3h1M540.9 247.9l-.3 2.5M541 249.4l.6 1M541.8 248.7l-1.1 1M544.9 244.5l.7-.1 .3 .2-.2 1.2a.66 .66 0 0 1-.6 .3 .66 .66 0 0 1-.5-.5l.1-.7zM547.1 244.6a.64 .64 0 0 1 1.1 .1l-.2 1.4M547.1 244.4l-.2 1.7M448 274.7l-.3 1.7M448.7 274.7l-.5 .2-.3 .3M450.6 274.9a.85 .85 0 0 0-1.3 .3l-.1 .8 .3 .3h.9M451.7 274.7l-.1 1.6a.7 .7 0 0 0 1-.1"/>
<path d="M452.8 274.7l-.2 1.7M454 274.7l-.2 1.7M454.1 273.9v.2M454.8 274.7h1M455.3 273.9l-.3 2.2 .1 .2 .5 .1M482.7 319.6a.64 .64 0 0 1 1 .1l-.1 1.3M436.9 333.1a1.21 1.21 0 0 1 1.3 .7 1.21 1.21 0 0 1-.4 1.4l-.6 .4h-.7zM438.7 338.5a.64 .64 0 0 1 1.1 .1l-.2 1.3M481.2 323.9a.64 .64 0 0 1 1.1 .1l-.2 1.3"/>
</g>
<g fill="#ffffc2" stroke="#ffffc2" stroke-width=".26">
<path d="M208.9 243.4h20.3v63.5h-20.3z"/>
<path d="M416.6 248.5h10.1v6.9h-10.1z"/>
<path d="M288.3 305.6h10.1v10.2h-10.1z"/>
<path d="M304.8 305.6h10.2v10.2h-10.2z"/>
<path d="M321.3 305.6h10.2v10.2h-10.2z"/>
<path d="M337.8 305.6h10.2v10.2h-10.2z"/>
<path d="M337.8 329.1h10.2v10.2h-10.2z"/>
<path d="M321.3 329.1h10.2v10.2h-10.2z"/>
<path d="M288.3 329.1h10.1v10.2h-10.1z"/>
<path d="M304.8 329.1h10.2v10.2h-10.2z"/>
<path d="M419.1 158.9h10.2v10.2h-10.2z"/>
<path d="M419.1 143h10.2v10.2h-10.2z"/>
<path d="M396.2 313.9h15.3v15.2h-15.3z"/>
</g>
<path d="M513.6 178.6v2.5M517.7 178.6v2.5M210.6 266.3a1.9 1.9 0 0 1 2.1-.6 1.9 1.9 0 0 1 1.3 1.8v7.6a1.9 1.9 0 0 1-1.9 1.9 1.9 1.9 0 0 1-1.9-1.9v-7.7zM215.8 267.5v1.3l2.5 2.5M218.3 263.7v8.9M220.9 266.2v1.3l-2.6 2.5" fill="none" stroke="#840000" stroke-width=".51"/>
<g fill="none" stroke="#000084" stroke-width=".26">
<path d="M233.7 278.3l1.2 1.2M233.7 273.2l1.2 1.3M233.7 270.7l1.2 1.2M234.9 278.3l-1.2 1.2M234.9 273.2l-1.2 1.3M234.9 270.7l-1.2 1.2M233.7 296.1l1.2 1.2M233.7 293.6l1.2 1.2M233.7 288.5l1.2 1.2M233.7 285.9l1.2 1.3M233.7 280.9l1.2 1.2M234.9 296.1l-1.2 1.2"/>
<path d="M234.9 293.6l-1.2 1.2M234.9 288.5l-1.2 1.2M234.9 285.9l-1.2 1.3M234.9 280.9l-1.2 1.2M233.7 303.7l1.2 1.2M233.7 301.2l1.2 1.2M234.9 303.7l-1.2 1.2M234.9 301.2l-1.2 1.2"/>
</g>
<path d="M202.6 311.3h13.9M202.6 311.3v24.8M216.5 336.1h-13.9M216.5 336.1v-24.8" fill="none" stroke="#0000c2" stroke-width=".26" stroke-dasharray=".5 .5"/>
<g fill="none" stroke="#0000c2" stroke-width=".51" stroke-dasharray="1.1 1.1">
<path d="M28.6 66.2h332.1M360.7 66.2v149.9M377.2 76.4v44.4M410.2 76.4v45.1M418.5 76.4h36.2M418.5 76.4v43.8M454.7 75.7v44.5M466.7 62.4h100.4M567.1 62.4v158.1M377.2 120.8h33M381.6 134.8h62.3M381.6 134.8v40.6"/>
<path d="M418.5 120.2h36.2M381.6 175.4h62.3M443.9 175.4v-40.6M381.6 181.1h61M381.6 181.1v45.1M442.6 181.1v45.1M28.6 216.1v-149.9M360.7 216.1h-332.1M38.1 239.6h134.6M172.7 239.6v113.6M187.3 233.2h71.8M259.1 233.2v117.5"/>
<path d="M271.8 232.6h47.6M321.9 231.9h47.7M381.6 226.2h61.6M383.5 230v50.2M384.8 230h72.4M459.1 230.7v49.5M466.7 220.5v-158.1M466.7 220.5h100.4M271.8 259.9v-27.3M319.4 259.9h-47.6M319.4 259.9v-27.3M321.9 259.2v-27.3"/>
<path d="M369.6 259.2h-47.7M369.6 259.2v-27.3M487 241.5v32.4M487 241.5h63.5M550.5 241.5v32.4M271.8 261.2h47.6M321.9 261.2h47.7M550.5 273.9h-63.5M271.1 291.6v61M271.8 288.5v-27.3M319.4 288.5h-47.6M319.4 288.5v-27.3"/>
<path d="M321.9 288.5v-27.3M369.6 291.6h-98.5M369.6 288.5h-47.7M369.6 288.5v-27.3M383.5 280.2h75.6M453.4 298v31.7M453.4 298h33M486.4 298v31.7M383.5 300.5v41.9M383.5 300.5h59.7M443.2 300.5v41.9M453.4 329.7h33"/>
<path d="M38.1 353.2v-113.6M172.7 353.2h-134.6M187.3 350.7v-117.5M259.1 350.7h-71.8M271.1 352.6h98.5M369.6 352.6v-61M383.5 342.4h59.7"/>
</g>
<g fill="none" stroke="#0000c2" stroke-width=".76">
<path d="M298.4 199.4l1.7 2.5M300.5 199.4l-2.4 2.5M538.5 209.8l.4-.2h.7l.3 .2 .2 .3-.3 2M540 210.5l-1.3 .2a.76 .76 0 0 0-.6 .6 .76 .76 0 0 0 .4 .8l1.3-.2M542.1 208.3l-.4 3.3 .5 .5M128.7 248.9l-.4 2.6M128.8 247.7l-.2 .2 .2 .1 .2-.1-.2-.2v.3M130.1 248.9l1.7 2.6M132.1 248.9l-2.3 2.6M316.4 254.7l-.3 2.5M317.5 254.7a1.19 1.19 0 0 0-1.2 .7M317.2 283.4a.91 .91 0 0 0-1.5 .6l.1 .3 .9 .2 .5 .6-.3 .5-.3 .2-1.1-.2"/>
<path d="M367.4 283.4a.91 .91 0 0 0-1.5 .6l.1 .3 .9 .2 .5 .6-.3 .5-.4 .2-1-.2M244.9 344.2l-.3 2.5M246 344.2a1.19 1.19 0 0 0-1.1 .7"/>
</g>
<path d="M377.2 76.4h33" fill="none" stroke="#0000c2" stroke-width=".51" stroke-dasharray="1.1 1.1 0 1.1"/>
<path d="M404.7 197.5h3.2z" fill="#840000" stroke="#840000" stroke-width=".51"/>
<use href="#words"/>
</svg>
